VERSION 5.8 ;
BUSBITCHARS "[]" ;
DIVIDERCHAR "/" ;
UNITS
    DATABASE MICRONS 1000 ;
END UNITS

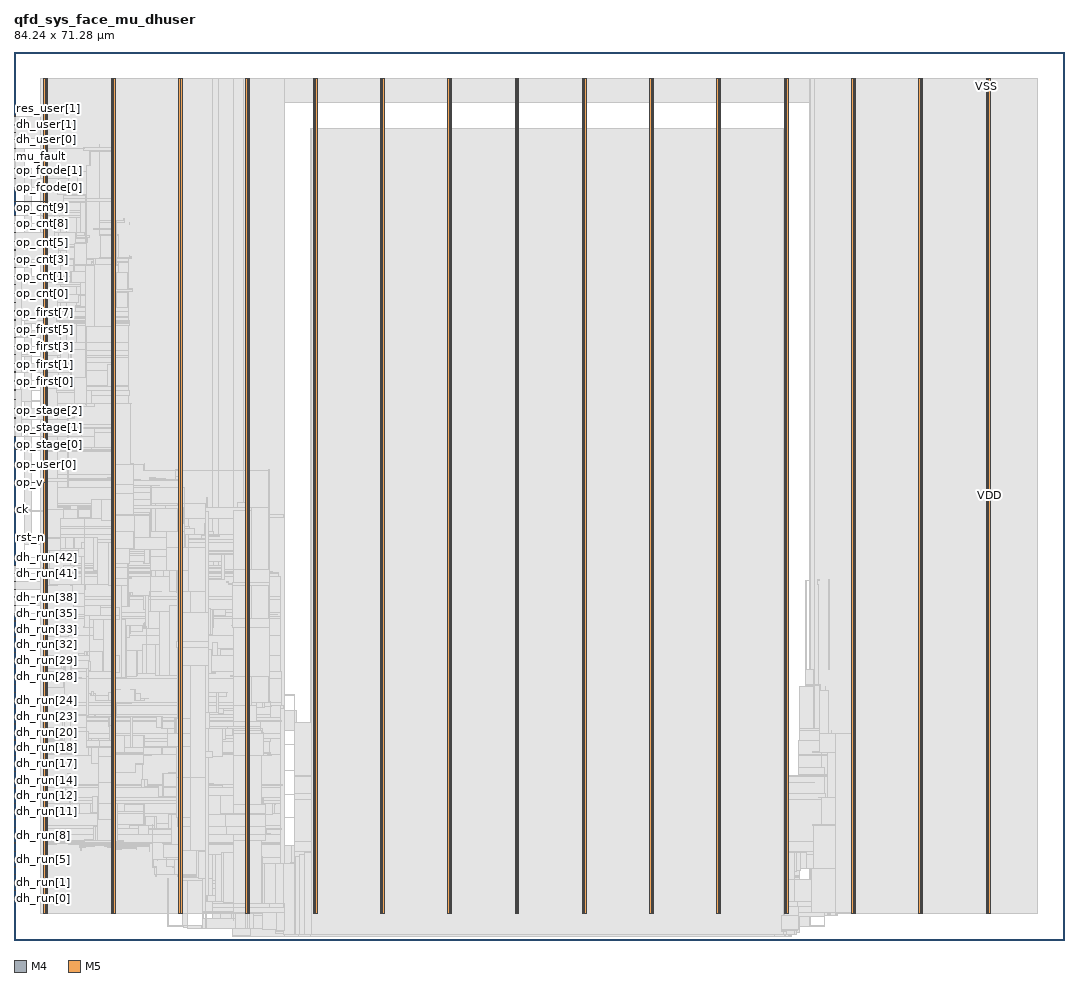
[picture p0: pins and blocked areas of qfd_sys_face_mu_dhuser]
MACRO qfd_sys_face_mu_dhuser
  FOREIGN qfd_sys_face_mu_dhuser 0 0 ;
  CLASS BLOCK ;
  SIZE 84.24 BY 71.28 ;
  PIN ck
    DIRECTION INPUT ;
    USE SIGNAL ;
    PORT
      LAYER M4 ;
        RECT  0 34.512 0.084 34.536 ;
    END
    PORT
      LAYER M4 ;
        RECT  0.06 34.512 0.097 34.536 ;
    END
  END ck
  PIN dh_run[0]
    DIRECTION INPUT ;
    USE SIGNAL ;
    PORT
      LAYER M4 ;
        RECT  0 3.312 0.084 3.336 ;
    END
  END dh_run[0]
  PIN dh_run[10]
    DIRECTION INPUT ;
    USE SIGNAL ;
    PORT
      LAYER M4 ;
        RECT  0 9.648 0.084 9.672 ;
    END
  END dh_run[10]
  PIN dh_run[11]
    DIRECTION INPUT ;
    USE SIGNAL ;
    PORT
      LAYER M4 ;
        RECT  0 10.32 0.084 10.344 ;
    END
  END dh_run[11]
  PIN dh_run[12]
    DIRECTION INPUT ;
    USE SIGNAL ;
    PORT
      LAYER M4 ;
        RECT  0 10.944 0.084 10.968 ;
    END
  END dh_run[12]
  PIN dh_run[13]
    DIRECTION INPUT ;
    USE SIGNAL ;
    PORT
      LAYER M4 ;
        RECT  0 11.568 0.084 11.592 ;
    END
  END dh_run[13]
  PIN dh_run[14]
    DIRECTION INPUT ;
    USE SIGNAL ;
    PORT
      LAYER M4 ;
        RECT  0 12.192 0.084 12.216 ;
    END
  END dh_run[14]
  PIN dh_run[15]
    DIRECTION INPUT ;
    USE SIGNAL ;
    PORT
      LAYER M4 ;
        RECT  0 12.864 0.084 12.888 ;
    END
  END dh_run[15]
  PIN dh_run[16]
    DIRECTION INPUT ;
    USE SIGNAL ;
    PORT
      LAYER M4 ;
        RECT  0 13.488 0.084 13.512 ;
    END
  END dh_run[16]
  PIN dh_run[17]
    DIRECTION INPUT ;
    USE SIGNAL ;
    PORT
      LAYER M4 ;
        RECT  0 14.112 0.084 14.136 ;
    END
  END dh_run[17]
  PIN dh_run[18]
    DIRECTION INPUT ;
    USE SIGNAL ;
    PORT
      LAYER M4 ;
        RECT  0 14.784 0.084 14.808 ;
    END
  END dh_run[18]
  PIN dh_run[19]
    DIRECTION INPUT ;
    USE SIGNAL ;
    PORT
      LAYER M4 ;
        RECT  0 15.408 0.084 15.432 ;
    END
  END dh_run[19]
  PIN dh_run[1]
    DIRECTION INPUT ;
    USE SIGNAL ;
    PORT
      LAYER M4 ;
        RECT  0 3.936 0.084 3.96 ;
    END
  END dh_run[1]
  PIN dh_run[20]
    DIRECTION INPUT ;
    USE SIGNAL ;
    PORT
      LAYER M4 ;
        RECT  0 16.032 0.084 16.056 ;
    END
  END dh_run[20]
  PIN dh_run[21]
    DIRECTION INPUT ;
    USE SIGNAL ;
    PORT
      LAYER M4 ;
        RECT  0 16.656 0.084 16.68 ;
    END
  END dh_run[21]
  PIN dh_run[22]
    DIRECTION INPUT ;
    USE SIGNAL ;
    PORT
      LAYER M4 ;
        RECT  0 17.328 0.084 17.352 ;
    END
  END dh_run[22]
  PIN dh_run[23]
    DIRECTION INPUT ;
    USE SIGNAL ;
    PORT
      LAYER M4 ;
        RECT  0 17.952 0.084 17.976 ;
    END
  END dh_run[23]
  PIN dh_run[24]
    DIRECTION INPUT ;
    USE SIGNAL ;
    PORT
      LAYER M4 ;
        RECT  0 18.576 0.084 18.6 ;
    END
  END dh_run[24]
  PIN dh_run[25]
    DIRECTION INPUT ;
    USE SIGNAL ;
    PORT
      LAYER M4 ;
        RECT  0 19.2 0.084 19.224 ;
    END
  END dh_run[25]
  PIN dh_run[26]
    DIRECTION INPUT ;
    USE SIGNAL ;
    PORT
      LAYER M4 ;
        RECT  0 19.872 0.084 19.896 ;
    END
  END dh_run[26]
  PIN dh_run[27]
    DIRECTION INPUT ;
    USE SIGNAL ;
    PORT
      LAYER M4 ;
        RECT  0 20.496 0.084 20.52 ;
    END
  END dh_run[27]
  PIN dh_run[28]
    DIRECTION INPUT ;
    USE SIGNAL ;
    PORT
      LAYER M4 ;
        RECT  0 21.12 0.084 21.144 ;
    END
  END dh_run[28]
  PIN dh_run[29]
    DIRECTION INPUT ;
    USE SIGNAL ;
    PORT
      LAYER M4 ;
        RECT  0 21.744 0.084 21.768 ;
    END
  END dh_run[29]
  PIN dh_run[2]
    DIRECTION INPUT ;
    USE SIGNAL ;
    PORT
      LAYER M4 ;
        RECT  0 4.56 0.084 4.584 ;
    END
  END dh_run[2]
  PIN dh_run[30]
    DIRECTION INPUT ;
    USE SIGNAL ;
    PORT
      LAYER M4 ;
        RECT  0 22.416 0.084 22.44 ;
    END
  END dh_run[30]
  PIN dh_run[31]
    DIRECTION INPUT ;
    USE SIGNAL ;
    PORT
      LAYER M4 ;
        RECT  0 23.04 0.084 23.064 ;
    END
  END dh_run[31]
  PIN dh_run[32]
    DIRECTION INPUT ;
    USE SIGNAL ;
    PORT
      LAYER M4 ;
        RECT  0 23.664 0.084 23.688 ;
    END
  END dh_run[32]
  PIN dh_run[33]
    DIRECTION INPUT ;
    USE SIGNAL ;
    PORT
      LAYER M4 ;
        RECT  0 24.288 0.084 24.312 ;
    END
  END dh_run[33]
  PIN dh_run[34]
    DIRECTION INPUT ;
    USE SIGNAL ;
    PORT
      LAYER M4 ;
        RECT  0 24.96 0.084 24.984 ;
    END
  END dh_run[34]
  PIN dh_run[35]
    DIRECTION INPUT ;
    USE SIGNAL ;
    PORT
      LAYER M4 ;
        RECT  0 25.584 0.084 25.608 ;
    END
  END dh_run[35]
  PIN dh_run[36]
    DIRECTION INPUT ;
    USE SIGNAL ;
    PORT
      LAYER M4 ;
        RECT  0 26.208 0.084 26.232 ;
    END
  END dh_run[36]
  PIN dh_run[37]
    DIRECTION INPUT ;
    USE SIGNAL ;
    PORT
      LAYER M4 ;
        RECT  0 26.832 0.084 26.856 ;
    END
  END dh_run[37]
  PIN dh_run[38]
    DIRECTION INPUT ;
    USE SIGNAL ;
    PORT
      LAYER M4 ;
        RECT  0 27.504 0.084 27.528 ;
    END
  END dh_run[38]
  PIN dh_run[39]
    DIRECTION INPUT ;
    USE SIGNAL ;
    PORT
      LAYER M4 ;
        RECT  0 28.128 0.084 28.152 ;
    END
  END dh_run[39]
  PIN dh_run[3]
    DIRECTION INPUT ;
    USE SIGNAL ;
    PORT
      LAYER M4 ;
        RECT  0 5.232 0.084 5.256 ;
    END
  END dh_run[3]
  PIN dh_run[40]
    DIRECTION INPUT ;
    USE SIGNAL ;
    PORT
      LAYER M4 ;
        RECT  0 28.752 0.084 28.776 ;
    END
  END dh_run[40]
  PIN dh_run[41]
    DIRECTION INPUT ;
    USE SIGNAL ;
    PORT
      LAYER M4 ;
        RECT  0 29.376 0.084 29.4 ;
    END
  END dh_run[41]
  PIN dh_run[42]
    DIRECTION INPUT ;
    USE SIGNAL ;
    PORT
      LAYER M4 ;
        RECT  0 30.048 0.084 30.072 ;
    END
  END dh_run[42]
  PIN dh_run[43]
    DIRECTION INPUT ;
    USE SIGNAL ;
    PORT
      LAYER M4 ;
        RECT  0 30.672 0.084 30.696 ;
    END
  END dh_run[43]
  PIN dh_run[4]
    DIRECTION INPUT ;
    USE SIGNAL ;
    PORT
      LAYER M4 ;
        RECT  0 5.856 0.084 5.88 ;
    END
  END dh_run[4]
  PIN dh_run[5]
    DIRECTION INPUT ;
    USE SIGNAL ;
    PORT
      LAYER M4 ;
        RECT  0 6.48 0.084 6.504 ;
    END
  END dh_run[5]
  PIN dh_run[6]
    DIRECTION INPUT ;
    USE SIGNAL ;
    PORT
      LAYER M4 ;
        RECT  0 7.104 0.084 7.128 ;
    END
  END dh_run[6]
  PIN dh_run[7]
    DIRECTION INPUT ;
    USE SIGNAL ;
    PORT
      LAYER M4 ;
        RECT  0 7.776 0.084 7.8 ;
    END
  END dh_run[7]
  PIN dh_run[8]
    DIRECTION INPUT ;
    USE SIGNAL ;
    PORT
      LAYER M4 ;
        RECT  0 8.4 0.084 8.424 ;
    END
  END dh_run[8]
  PIN dh_run[9]
    DIRECTION INPUT ;
    USE SIGNAL ;
    PORT
      LAYER M4 ;
        RECT  0 9.024 0.084 9.048 ;
    END
  END dh_run[9]
  PIN dh_user[0]
    DIRECTION OUTPUT ;
    USE SIGNAL ;
    PORT
      LAYER M4 ;
        RECT  0 64.224 0.084 64.248 ;
    END
  END dh_user[0]
  PIN dh_user[1]
    DIRECTION OUTPUT ;
    USE SIGNAL ;
    PORT
      LAYER M4 ;
        RECT  0 64.752 0.084 64.776 ;
    END
  END dh_user[1]
  PIN mu_fault
    DIRECTION OUTPUT ;
    USE SIGNAL ;
    PORT
      LAYER M4 ;
        RECT  0 63.504 0.084 63.528 ;
    END
  END mu_fault
  PIN op_cnt[0]
    DIRECTION OUTPUT ;
    USE SIGNAL ;
    PORT
      LAYER M4 ;
        RECT  0 51.84 0.084 51.864 ;
    END
  END op_cnt[0]
  PIN op_cnt[1]
    DIRECTION OUTPUT ;
    USE SIGNAL ;
    PORT
      LAYER M4 ;
        RECT  0 52.56 0.084 52.584 ;
    END
  END op_cnt[1]
  PIN op_cnt[2]
    DIRECTION OUTPUT ;
    USE SIGNAL ;
    PORT
      LAYER M4 ;
        RECT  0 53.232 0.084 53.256 ;
    END
  END op_cnt[2]
  PIN op_cnt[3]
    DIRECTION OUTPUT ;
    USE SIGNAL ;
    PORT
      LAYER M4 ;
        RECT  0 53.952 0.084 53.976 ;
    END
  END op_cnt[3]
  PIN op_cnt[4]
    DIRECTION OUTPUT ;
    USE SIGNAL ;
    PORT
      LAYER M4 ;
        RECT  0 54.624 0.084 54.648 ;
    END
  END op_cnt[4]
  PIN op_cnt[5]
    DIRECTION OUTPUT ;
    USE SIGNAL ;
    PORT
      LAYER M4 ;
        RECT  0 55.344 0.084 55.368 ;
    END
  END op_cnt[5]
  PIN op_cnt[6]
    DIRECTION OUTPUT ;
    USE SIGNAL ;
    PORT
      LAYER M4 ;
        RECT  0 56.016 0.084 56.04 ;
    END
  END op_cnt[6]
  PIN op_cnt[7]
    DIRECTION OUTPUT ;
    USE SIGNAL ;
    PORT
      LAYER M4 ;
        RECT  0 56.736 0.084 56.76 ;
    END
  END op_cnt[7]
  PIN op_cnt[8]
    DIRECTION OUTPUT ;
    USE SIGNAL ;
    PORT
      LAYER M4 ;
        RECT  0 57.456 0.084 57.48 ;
    END
  END op_cnt[8]
  PIN op_cnt[9]
    DIRECTION OUTPUT ;
    USE SIGNAL ;
    PORT
      LAYER M4 ;
        RECT  0 58.128 0.084 58.152 ;
    END
  END op_cnt[9]
  PIN op_fcode[0]
    DIRECTION OUTPUT ;
    USE SIGNAL ;
    PORT
      LAYER M4 ;
        RECT  0 60.384 0.084 60.408 ;
    END
  END op_fcode[0]
  PIN op_fcode[1]
    DIRECTION OUTPUT ;
    USE SIGNAL ;
    PORT
      LAYER M4 ;
        RECT  0 61.104 0.084 61.128 ;
    END
  END op_fcode[1]
  PIN op_fcode[2]
    DIRECTION OUTPUT ;
    USE SIGNAL ;
    PORT
      LAYER M4 ;
        RECT  0 61.872 0.084 61.896 ;
    END
  END op_fcode[2]
  PIN op_fcode[3]
    DIRECTION OUTPUT ;
    USE SIGNAL ;
    PORT
      LAYER M4 ;
        RECT  0 62.592 0.084 62.616 ;
    END
  END op_fcode[3]
  PIN op_ff
    DIRECTION OUTPUT ;
    USE SIGNAL ;
    PORT
      LAYER M4 ;
        RECT  0 59.232 0.084 59.256 ;
    END
    PORT
      LAYER M4 ;
        RECT  0.06 59.232 2.408 59.256 ;
    END
  END op_ff
  PIN op_first[0]
    DIRECTION OUTPUT ;
    USE SIGNAL ;
    PORT
      LAYER M4 ;
        RECT  0 44.832 0.084 44.856 ;
    END
  END op_first[0]
  PIN op_first[1]
    DIRECTION OUTPUT ;
    USE SIGNAL ;
    PORT
      LAYER M4 ;
        RECT  0 45.552 0.084 45.576 ;
    END
  END op_first[1]
  PIN op_first[2]
    DIRECTION OUTPUT ;
    USE SIGNAL ;
    PORT
      LAYER M4 ;
        RECT  0 46.224 0.084 46.248 ;
    END
  END op_first[2]
  PIN op_first[3]
    DIRECTION OUTPUT ;
    USE SIGNAL ;
    PORT
      LAYER M4 ;
        RECT  0 46.944 0.084 46.968 ;
    END
  END op_first[3]
  PIN op_first[4]
    DIRECTION OUTPUT ;
    USE SIGNAL ;
    PORT
      LAYER M4 ;
        RECT  0 47.616 0.084 47.64 ;
    END
  END op_first[4]
  PIN op_first[5]
    DIRECTION OUTPUT ;
    USE SIGNAL ;
    PORT
      LAYER M4 ;
        RECT  0 48.336 0.084 48.36 ;
    END
  END op_first[5]
  PIN op_first[6]
    DIRECTION OUTPUT ;
    USE SIGNAL ;
    PORT
      LAYER M4 ;
        RECT  0 49.056 0.084 49.08 ;
    END
  END op_first[6]
  PIN op_first[7]
    DIRECTION OUTPUT ;
    USE SIGNAL ;
    PORT
      LAYER M4 ;
        RECT  0 49.728 0.084 49.752 ;
    END
  END op_first[7]
  PIN op_first[8]
    DIRECTION OUTPUT ;
    USE SIGNAL ;
    PORT
      LAYER M4 ;
        RECT  0 50.448 0.084 50.472 ;
    END
  END op_first[8]
  PIN op_first[9]
    DIRECTION OUTPUT ;
    USE SIGNAL ;
    PORT
      LAYER M4 ;
        RECT  0 51.12 0.084 51.144 ;
    END
  END op_first[9]
  PIN op_stage[0]
    DIRECTION OUTPUT ;
    USE SIGNAL ;
    PORT
      LAYER M4 ;
        RECT  0 40.368 0.084 40.392 ;
    END
  END op_stage[0]
  PIN op_stage[1]
    DIRECTION OUTPUT ;
    USE SIGNAL ;
    PORT
      LAYER M4 ;
        RECT  0 41.136 0.084 41.16 ;
    END
  END op_stage[1]
  PIN op_stage[2]
    DIRECTION OUTPUT ;
    USE SIGNAL ;
    PORT
      LAYER M4 ;
        RECT  0 41.856 0.084 41.88 ;
    END
  END op_stage[2]
  PIN op_stage[3]
    DIRECTION OUTPUT ;
    USE SIGNAL ;
    PORT
      LAYER M4 ;
        RECT  0 42.624 0.084 42.648 ;
    END
  END op_stage[3]
  PIN op_stage[4]
    DIRECTION OUTPUT ;
    USE SIGNAL ;
    PORT
      LAYER M4 ;
        RECT  0 43.344 0.084 43.368 ;
    END
  END op_stage[4]
  PIN op_stage[5]
    DIRECTION OUTPUT ;
    USE SIGNAL ;
    PORT
      LAYER M4 ;
        RECT  0 44.112 0.084 44.136 ;
    END
  END op_stage[5]
  PIN op_user[0]
    DIRECTION OUTPUT ;
    USE SIGNAL ;
    PORT
      LAYER M4 ;
        RECT  0 38.112 0.084 38.136 ;
    END
    PORT
      LAYER M4 ;
        RECT  0.06 38.112 2.408 38.136 ;
    END
  END op_user[0]
  PIN op_user[1]
    DIRECTION OUTPUT ;
    USE SIGNAL ;
    PORT
      LAYER M4 ;
        RECT  0 39.36 0.084 39.384 ;
    END
    PORT
      LAYER M4 ;
        RECT  0.06 39.36 0.569 39.384 ;
    END
  END op_user[1]
  PIN op_v
    DIRECTION OUTPUT ;
    USE SIGNAL ;
    PORT
      LAYER M4 ;
        RECT  0 36.72 0.084 36.744 ;
    END
    PORT
      LAYER M4 ;
        RECT  0.06 36.72 2.408 36.744 ;
    END
  END op_v
  PIN res_user[0]
    DIRECTION OUTPUT ;
    USE SIGNAL ;
    PORT
      LAYER M4 ;
        RECT  0 65.376 0.084 65.4 ;
    END
  END res_user[0]
  PIN res_user[1]
    DIRECTION OUTPUT ;
    USE SIGNAL ;
    PORT
      LAYER M4 ;
        RECT  0 66.096 0.084 66.12 ;
    END
  END res_user[1]
  PIN rst_n
    DIRECTION INPUT ;
    USE SIGNAL ;
    PORT
      LAYER M4 ;
        RECT  0 32.256 0.084 32.28 ;
    END
    PORT
      LAYER M4 ;
        RECT  0.06 32.256 2.408 32.28 ;
    END
  END rst_n
  PIN VDD
    DIRECTION INOUT ;
    USE POWER ;
    PORT
      LAYER M5 ;
        RECT  78.192 2.151 78.312 69.129 ;
        RECT  72.792 2.151 72.912 69.129 ;
        RECT  67.392 2.151 67.512 69.129 ;
        RECT  61.992 2.151 62.112 69.129 ;
        RECT  56.592 2.151 56.712 69.129 ;
        RECT  51.192 2.151 51.312 69.129 ;
        RECT  45.792 2.151 45.912 69.129 ;
        RECT  40.392 2.151 40.512 69.129 ;
        RECT  34.992 2.151 35.112 69.129 ;
        RECT  29.592 2.151 29.712 69.129 ;
        RECT  24.192 2.151 24.312 69.129 ;
        RECT  18.792 2.151 18.912 69.129 ;
        RECT  13.392 2.151 13.512 69.129 ;
        RECT  7.992 2.151 8.112 69.129 ;
        RECT  2.592 2.151 2.712 69.129 ;
    END
  END VDD
  PIN VSS
    DIRECTION INOUT ;
    USE GROUND ;
    PORT
      LAYER M5 ;
        RECT  78 2.137 78.12 69.143 ;
        RECT  72.6 2.137 72.72 69.143 ;
        RECT  67.2 2.137 67.32 69.143 ;
        RECT  61.8 2.151 61.92 69.143 ;
        RECT  56.4 2.151 56.52 69.143 ;
        RECT  51 2.151 51.12 69.143 ;
        RECT  45.6 2.151 45.72 69.143 ;
        RECT  40.2 2.151 40.32 69.143 ;
        RECT  34.8 2.151 34.92 69.143 ;
        RECT  29.4 2.151 29.52 69.143 ;
        RECT  24 2.151 24.12 69.143 ;
        RECT  18.6 2.137 18.72 69.143 ;
        RECT  13.2 2.137 13.32 69.143 ;
        RECT  7.8 2.137 7.92 69.143 ;
        RECT  2.4 2.137 2.52 69.143 ;
    END
  END VSS
  # OT_OBS_CLOSED layer=M5 d_um=1.536 added=63
  OBS
    LAYER RVTN ;
     RECT  2.16 2.16 21.708 2.295 ;
     RECT  63.828 2.16 82.08 2.295 ;
     RECT  2.16 2.565 21.708 2.835 ;
     RECT  63.828 2.565 82.08 2.835 ;
     RECT  2.16 3.105 21.708 3.375 ;
     RECT  63.828 3.105 82.08 3.375 ;
     RECT  2.16 3.645 21.708 3.915 ;
     RECT  63.828 3.645 82.08 3.915 ;
     RECT  2.16 4.185 21.708 4.455 ;
     RECT  63.828 4.185 82.08 4.455 ;
     RECT  2.16 4.725 21.708 4.995 ;
     RECT  63.828 4.725 82.08 4.995 ;
     RECT  2.16 5.265 21.708 5.535 ;
     RECT  63.828 5.265 82.08 5.535 ;
     RECT  2.16 5.805 21.708 6.075 ;
     RECT  63.828 5.805 82.08 6.075 ;
     RECT  2.16 6.345 21.708 6.615 ;
     RECT  63.828 6.345 82.08 6.615 ;
     RECT  2.16 6.885 21.708 7.155 ;
     RECT  63.828 6.885 82.08 7.155 ;
     RECT  2.16 7.425 21.708 7.695 ;
     RECT  63.828 7.425 82.08 7.695 ;
     RECT  2.16 7.965 21.708 8.235 ;
     RECT  63.828 7.965 82.08 8.235 ;
     RECT  2.16 8.505 21.708 8.775 ;
     RECT  63.828 8.505 82.08 8.775 ;
     RECT  2.16 9.045 21.708 9.315 ;
     RECT  63.828 9.045 82.08 9.315 ;
     RECT  2.16 9.585 21.708 9.855 ;
     RECT  63.828 9.585 82.08 9.855 ;
     RECT  2.16 10.125 21.708 10.395 ;
     RECT  63.828 10.125 82.08 10.395 ;
     RECT  2.16 10.665 21.708 10.935 ;
     RECT  63.828 10.665 82.08 10.935 ;
     RECT  2.16 11.205 21.708 11.475 ;
     RECT  63.828 11.205 82.08 11.475 ;
     RECT  2.16 11.745 21.708 12.015 ;
     RECT  63.828 11.745 82.08 12.015 ;
     RECT  2.16 12.285 21.708 12.555 ;
     RECT  63.828 12.285 82.08 12.555 ;
     RECT  2.16 12.825 21.708 13.095 ;
     RECT  63.828 12.825 82.08 13.095 ;
     RECT  2.16 13.365 21.708 13.635 ;
     RECT  63.828 13.365 82.08 13.635 ;
     RECT  2.16 13.905 21.708 14.175 ;
     RECT  63.828 13.905 82.08 14.175 ;
     RECT  2.16 14.445 21.708 14.715 ;
     RECT  63.828 14.445 82.08 14.715 ;
     RECT  2.16 14.985 21.708 15.255 ;
     RECT  63.828 14.985 82.08 15.255 ;
     RECT  2.16 15.525 21.708 15.795 ;
     RECT  63.828 15.525 82.08 15.795 ;
     RECT  2.16 16.065 21.708 16.335 ;
     RECT  63.828 16.065 82.08 16.335 ;
     RECT  2.16 16.605 21.708 16.875 ;
     RECT  63.828 16.605 82.08 16.875 ;
     RECT  2.16 17.145 21.708 17.415 ;
     RECT  63.828 17.145 82.08 17.415 ;
     RECT  2.16 17.685 21.708 17.955 ;
     RECT  63.828 17.685 82.08 17.955 ;
     RECT  2.16 18.225 21.708 18.495 ;
     RECT  63.828 18.225 82.08 18.495 ;
     RECT  2.16 18.765 21.708 19.035 ;
     RECT  63.828 18.765 82.08 19.035 ;
     RECT  2.16 19.305 21.708 19.575 ;
     RECT  63.828 19.305 82.08 19.575 ;
     RECT  2.16 19.845 21.708 20.115 ;
     RECT  63.828 19.845 82.08 20.115 ;
     RECT  2.16 20.385 21.708 20.655 ;
     RECT  63.828 20.385 82.08 20.655 ;
     RECT  2.16 20.925 21.708 21.195 ;
     RECT  63.828 20.925 82.08 21.195 ;
     RECT  2.16 21.465 21.708 21.735 ;
     RECT  63.828 21.465 82.08 21.735 ;
     RECT  2.16 22.005 21.708 22.275 ;
     RECT  63.828 22.005 82.08 22.275 ;
     RECT  2.16 22.545 21.708 22.815 ;
     RECT  63.828 22.545 82.08 22.815 ;
     RECT  2.16 23.085 21.708 23.355 ;
     RECT  63.828 23.085 82.08 23.355 ;
     RECT  2.16 23.625 21.708 23.895 ;
     RECT  63.828 23.625 82.08 23.895 ;
     RECT  2.16 24.165 21.708 24.435 ;
     RECT  63.828 24.165 82.08 24.435 ;
     RECT  2.16 24.705 21.708 24.975 ;
     RECT  63.828 24.705 82.08 24.975 ;
     RECT  2.16 25.245 21.708 25.515 ;
     RECT  63.828 25.245 82.08 25.515 ;
     RECT  2.16 25.785 21.708 26.055 ;
     RECT  63.828 25.785 82.08 26.055 ;
     RECT  2.16 26.325 21.708 26.595 ;
     RECT  63.828 26.325 82.08 26.595 ;
     RECT  2.16 26.865 21.708 27.135 ;
     RECT  63.828 26.865 82.08 27.135 ;
     RECT  2.16 27.405 21.708 27.675 ;
     RECT  63.828 27.405 82.08 27.675 ;
     RECT  2.16 27.945 21.708 28.215 ;
     RECT  63.828 27.945 82.08 28.215 ;
     RECT  2.16 28.485 21.708 28.755 ;
     RECT  63.828 28.485 82.08 28.755 ;
     RECT  2.16 29.025 21.708 29.295 ;
     RECT  63.828 29.025 82.08 29.295 ;
     RECT  2.16 29.565 21.708 29.835 ;
     RECT  63.828 29.565 82.08 29.835 ;
     RECT  2.16 30.105 21.708 30.375 ;
     RECT  63.828 30.105 82.08 30.375 ;
     RECT  2.16 30.645 21.708 30.915 ;
     RECT  63.828 30.645 82.08 30.915 ;
     RECT  2.16 31.185 21.708 31.455 ;
     RECT  63.828 31.185 82.08 31.455 ;
     RECT  2.16 31.725 21.708 31.995 ;
     RECT  63.828 31.725 82.08 31.995 ;
     RECT  2.16 32.265 21.708 32.535 ;
     RECT  63.828 32.265 82.08 32.535 ;
     RECT  2.16 32.805 21.708 33.075 ;
     RECT  63.828 32.805 82.08 33.075 ;
     RECT  2.16 33.345 21.708 33.615 ;
     RECT  63.828 33.345 82.08 33.615 ;
     RECT  2.16 33.885 21.708 34.155 ;
     RECT  63.828 33.885 82.08 34.155 ;
     RECT  2.16 34.425 21.708 34.695 ;
     RECT  63.828 34.425 82.08 34.695 ;
     RECT  2.16 34.965 21.708 35.235 ;
     RECT  63.828 34.965 82.08 35.235 ;
     RECT  2.16 35.505 21.708 35.775 ;
     RECT  63.828 35.505 82.08 35.775 ;
     RECT  2.16 36.045 21.708 36.315 ;
     RECT  63.828 36.045 82.08 36.315 ;
     RECT  2.16 36.585 21.708 36.855 ;
     RECT  63.828 36.585 82.08 36.855 ;
     RECT  2.16 37.125 21.708 37.395 ;
     RECT  63.828 37.125 82.08 37.395 ;
     RECT  2.16 37.665 21.708 37.935 ;
     RECT  63.828 37.665 82.08 37.935 ;
     RECT  2.16 38.205 21.708 38.475 ;
     RECT  63.828 38.205 82.08 38.475 ;
     RECT  2.16 38.745 21.708 39.015 ;
     RECT  63.828 38.745 82.08 39.015 ;
     RECT  2.16 39.285 21.708 39.555 ;
     RECT  63.828 39.285 82.08 39.555 ;
     RECT  2.16 39.825 21.708 40.095 ;
     RECT  63.828 39.825 82.08 40.095 ;
     RECT  2.16 40.365 21.708 40.635 ;
     RECT  63.828 40.365 82.08 40.635 ;
     RECT  2.16 40.905 21.708 41.175 ;
     RECT  63.828 40.905 82.08 41.175 ;
     RECT  2.16 41.445 21.708 41.715 ;
     RECT  63.828 41.445 82.08 41.715 ;
     RECT  2.16 41.985 21.708 42.255 ;
     RECT  63.828 41.985 82.08 42.255 ;
     RECT  2.16 42.525 21.708 42.795 ;
     RECT  63.828 42.525 82.08 42.795 ;
     RECT  2.16 43.065 21.708 43.335 ;
     RECT  63.828 43.065 82.08 43.335 ;
     RECT  2.16 43.605 21.708 43.875 ;
     RECT  63.828 43.605 82.08 43.875 ;
     RECT  2.16 44.145 21.708 44.415 ;
     RECT  63.828 44.145 82.08 44.415 ;
     RECT  2.16 44.685 21.708 44.955 ;
     RECT  63.828 44.685 82.08 44.955 ;
     RECT  2.16 45.225 21.708 45.495 ;
     RECT  63.828 45.225 82.08 45.495 ;
     RECT  2.16 45.765 21.708 46.035 ;
     RECT  63.828 45.765 82.08 46.035 ;
     RECT  2.16 46.305 21.708 46.575 ;
     RECT  63.828 46.305 82.08 46.575 ;
     RECT  2.16 46.845 21.708 47.115 ;
     RECT  63.828 46.845 82.08 47.115 ;
     RECT  2.16 47.385 21.708 47.655 ;
     RECT  63.828 47.385 82.08 47.655 ;
     RECT  2.16 47.925 21.708 48.195 ;
     RECT  63.828 47.925 82.08 48.195 ;
     RECT  2.16 48.465 21.708 48.735 ;
     RECT  63.828 48.465 82.08 48.735 ;
     RECT  2.16 49.005 21.708 49.275 ;
     RECT  63.828 49.005 82.08 49.275 ;
     RECT  2.16 49.545 21.708 49.815 ;
     RECT  63.828 49.545 82.08 49.815 ;
     RECT  2.16 50.085 21.708 50.355 ;
     RECT  63.828 50.085 82.08 50.355 ;
     RECT  2.16 50.625 21.708 50.895 ;
     RECT  63.828 50.625 82.08 50.895 ;
     RECT  2.16 51.165 21.708 51.435 ;
     RECT  63.828 51.165 82.08 51.435 ;
     RECT  2.16 51.705 21.708 51.975 ;
     RECT  63.828 51.705 82.08 51.975 ;
     RECT  2.16 52.245 21.708 52.515 ;
     RECT  63.828 52.245 82.08 52.515 ;
     RECT  2.16 52.785 21.708 53.055 ;
     RECT  63.828 52.785 82.08 53.055 ;
     RECT  2.16 53.325 21.708 53.595 ;
     RECT  63.828 53.325 82.08 53.595 ;
     RECT  2.16 53.865 21.708 54.135 ;
     RECT  63.828 53.865 82.08 54.135 ;
     RECT  2.16 54.405 21.708 54.675 ;
     RECT  63.828 54.405 82.08 54.675 ;
     RECT  2.16 54.945 21.708 55.215 ;
     RECT  63.828 54.945 82.08 55.215 ;
     RECT  2.16 55.485 21.708 55.755 ;
     RECT  63.828 55.485 82.08 55.755 ;
     RECT  2.16 56.025 21.708 56.295 ;
     RECT  63.828 56.025 82.08 56.295 ;
     RECT  2.16 56.565 21.708 56.835 ;
     RECT  63.828 56.565 82.08 56.835 ;
     RECT  2.16 57.105 21.708 57.375 ;
     RECT  63.828 57.105 82.08 57.375 ;
     RECT  2.16 57.645 21.708 57.915 ;
     RECT  63.828 57.645 82.08 57.915 ;
     RECT  2.16 58.185 21.708 58.455 ;
     RECT  63.828 58.185 82.08 58.455 ;
     RECT  2.16 58.725 21.708 58.995 ;
     RECT  63.828 58.725 82.08 58.995 ;
     RECT  2.16 59.265 21.708 59.535 ;
     RECT  63.828 59.265 82.08 59.535 ;
     RECT  2.16 59.805 21.708 60.075 ;
     RECT  63.828 59.805 82.08 60.075 ;
     RECT  2.16 60.345 21.708 60.615 ;
     RECT  63.828 60.345 82.08 60.615 ;
     RECT  2.16 60.885 21.708 61.155 ;
     RECT  63.828 60.885 82.08 61.155 ;
     RECT  2.16 61.425 21.708 61.695 ;
     RECT  63.828 61.425 82.08 61.695 ;
     RECT  2.16 61.965 21.708 62.235 ;
     RECT  63.828 61.965 82.08 62.235 ;
     RECT  2.16 62.505 21.708 62.775 ;
     RECT  63.828 62.505 82.08 62.775 ;
     RECT  2.16 63.045 21.708 63.315 ;
     RECT  63.828 63.045 82.08 63.315 ;
     RECT  2.16 63.585 21.708 63.855 ;
     RECT  63.828 63.585 82.08 63.855 ;
     RECT  2.16 64.125 21.708 64.395 ;
     RECT  63.828 64.125 82.08 64.395 ;
     RECT  2.16 64.665 21.708 64.935 ;
     RECT  63.828 64.665 82.08 64.935 ;
     RECT  2.16 65.205 21.708 65.475 ;
     RECT  63.828 65.205 82.08 65.475 ;
     RECT  2.16 65.745 21.708 66.015 ;
     RECT  63.828 65.745 82.08 66.015 ;
     RECT  2.16 66.285 21.708 66.555 ;
     RECT  63.828 66.285 82.08 66.555 ;
     RECT  2.16 66.825 21.708 67.095 ;
     RECT  63.828 66.825 82.08 67.095 ;
     RECT  2.16 67.365 82.08 67.635 ;
     RECT  2.16 67.905 82.08 68.175 ;
     RECT  2.16 68.445 82.08 68.715 ;
     RECT  2.16 68.985 82.08 69.12 ;
    LAYER RVTP ;
     RECT  2.16 2.295 21.708 2.565 ;
     RECT  63.828 2.295 82.08 2.565 ;
     RECT  2.16 2.835 21.708 3.105 ;
     RECT  63.828 2.835 82.08 3.105 ;
     RECT  2.16 3.375 21.708 3.645 ;
     RECT  63.828 3.375 82.08 3.645 ;
     RECT  2.16 3.915 21.708 4.185 ;
     RECT  63.828 3.915 82.08 4.185 ;
     RECT  2.16 4.455 21.708 4.725 ;
     RECT  63.828 4.455 82.08 4.725 ;
     RECT  2.16 4.995 21.708 5.265 ;
     RECT  63.828 4.995 82.08 5.265 ;
     RECT  2.16 5.535 21.708 5.805 ;
     RECT  63.828 5.535 82.08 5.805 ;
     RECT  2.16 6.075 21.708 6.345 ;
     RECT  63.828 6.075 82.08 6.345 ;
     RECT  2.16 6.615 21.708 6.885 ;
     RECT  63.828 6.615 82.08 6.885 ;
     RECT  2.16 7.155 21.708 7.425 ;
     RECT  63.828 7.155 82.08 7.425 ;
     RECT  2.16 7.695 21.708 7.965 ;
     RECT  63.828 7.695 82.08 7.965 ;
     RECT  2.16 8.235 21.708 8.505 ;
     RECT  63.828 8.235 82.08 8.505 ;
     RECT  2.16 8.775 21.708 9.045 ;
     RECT  63.828 8.775 82.08 9.045 ;
     RECT  2.16 9.315 21.708 9.585 ;
     RECT  63.828 9.315 82.08 9.585 ;
     RECT  2.16 9.855 21.708 10.125 ;
     RECT  63.828 9.855 82.08 10.125 ;
     RECT  2.16 10.395 21.708 10.665 ;
     RECT  63.828 10.395 82.08 10.665 ;
     RECT  2.16 10.935 21.708 11.205 ;
     RECT  63.828 10.935 82.08 11.205 ;
     RECT  2.16 11.475 21.708 11.745 ;
     RECT  63.828 11.475 82.08 11.745 ;
     RECT  2.16 12.015 21.708 12.285 ;
     RECT  63.828 12.015 82.08 12.285 ;
     RECT  2.16 12.555 21.708 12.825 ;
     RECT  63.828 12.555 82.08 12.825 ;
     RECT  2.16 13.095 21.708 13.365 ;
     RECT  63.828 13.095 82.08 13.365 ;
     RECT  2.16 13.635 21.708 13.905 ;
     RECT  63.828 13.635 82.08 13.905 ;
     RECT  2.16 14.175 21.708 14.445 ;
     RECT  63.828 14.175 82.08 14.445 ;
     RECT  2.16 14.715 21.708 14.985 ;
     RECT  63.828 14.715 82.08 14.985 ;
     RECT  2.16 15.255 21.708 15.525 ;
     RECT  63.828 15.255 82.08 15.525 ;
     RECT  2.16 15.795 21.708 16.065 ;
     RECT  63.828 15.795 82.08 16.065 ;
     RECT  2.16 16.335 21.708 16.605 ;
     RECT  63.828 16.335 82.08 16.605 ;
     RECT  2.16 16.875 21.708 17.145 ;
     RECT  63.828 16.875 82.08 17.145 ;
     RECT  2.16 17.415 21.708 17.685 ;
     RECT  63.828 17.415 82.08 17.685 ;
     RECT  2.16 17.955 21.708 18.225 ;
     RECT  63.828 17.955 82.08 18.225 ;
     RECT  2.16 18.495 21.708 18.765 ;
     RECT  63.828 18.495 82.08 18.765 ;
     RECT  2.16 19.035 21.708 19.305 ;
     RECT  63.828 19.035 82.08 19.305 ;
     RECT  2.16 19.575 21.708 19.845 ;
     RECT  63.828 19.575 82.08 19.845 ;
     RECT  2.16 20.115 21.708 20.385 ;
     RECT  63.828 20.115 82.08 20.385 ;
     RECT  2.16 20.655 21.708 20.925 ;
     RECT  63.828 20.655 82.08 20.925 ;
     RECT  2.16 21.195 21.708 21.465 ;
     RECT  63.828 21.195 82.08 21.465 ;
     RECT  2.16 21.735 21.708 22.005 ;
     RECT  63.828 21.735 82.08 22.005 ;
     RECT  2.16 22.275 21.708 22.545 ;
     RECT  63.828 22.275 82.08 22.545 ;
     RECT  2.16 22.815 21.708 23.085 ;
     RECT  63.828 22.815 82.08 23.085 ;
     RECT  2.16 23.355 21.708 23.625 ;
     RECT  63.828 23.355 82.08 23.625 ;
     RECT  2.16 23.895 21.708 24.165 ;
     RECT  63.828 23.895 82.08 24.165 ;
     RECT  2.16 24.435 21.708 24.705 ;
     RECT  63.828 24.435 82.08 24.705 ;
     RECT  2.16 24.975 21.708 25.245 ;
     RECT  63.828 24.975 82.08 25.245 ;
     RECT  2.16 25.515 21.708 25.785 ;
     RECT  63.828 25.515 82.08 25.785 ;
     RECT  2.16 26.055 21.708 26.325 ;
     RECT  63.828 26.055 82.08 26.325 ;
     RECT  2.16 26.595 21.708 26.865 ;
     RECT  63.828 26.595 82.08 26.865 ;
     RECT  2.16 27.135 21.708 27.405 ;
     RECT  63.828 27.135 82.08 27.405 ;
     RECT  2.16 27.675 21.708 27.945 ;
     RECT  63.828 27.675 82.08 27.945 ;
     RECT  2.16 28.215 21.708 28.485 ;
     RECT  63.828 28.215 82.08 28.485 ;
     RECT  2.16 28.755 21.708 29.025 ;
     RECT  63.828 28.755 82.08 29.025 ;
     RECT  2.16 29.295 21.708 29.565 ;
     RECT  63.828 29.295 82.08 29.565 ;
     RECT  2.16 29.835 21.708 30.105 ;
     RECT  63.828 29.835 82.08 30.105 ;
     RECT  2.16 30.375 21.708 30.645 ;
     RECT  63.828 30.375 82.08 30.645 ;
     RECT  2.16 30.915 21.708 31.185 ;
     RECT  63.828 30.915 82.08 31.185 ;
     RECT  2.16 31.455 21.708 31.725 ;
     RECT  63.828 31.455 82.08 31.725 ;
     RECT  2.16 31.995 21.708 32.265 ;
     RECT  63.828 31.995 82.08 32.265 ;
     RECT  2.16 32.535 21.708 32.805 ;
     RECT  63.828 32.535 82.08 32.805 ;
     RECT  2.16 33.075 21.708 33.345 ;
     RECT  63.828 33.075 82.08 33.345 ;
     RECT  2.16 33.615 21.708 33.885 ;
     RECT  63.828 33.615 82.08 33.885 ;
     RECT  2.16 34.155 21.708 34.425 ;
     RECT  63.828 34.155 82.08 34.425 ;
     RECT  2.16 34.695 21.708 34.965 ;
     RECT  63.828 34.695 82.08 34.965 ;
     RECT  2.16 35.235 21.708 35.505 ;
     RECT  63.828 35.235 82.08 35.505 ;
     RECT  2.16 35.775 21.708 36.045 ;
     RECT  63.828 35.775 82.08 36.045 ;
     RECT  2.16 36.315 21.708 36.585 ;
     RECT  63.828 36.315 82.08 36.585 ;
     RECT  2.16 36.855 21.708 37.125 ;
     RECT  63.828 36.855 82.08 37.125 ;
     RECT  2.16 37.395 21.708 37.665 ;
     RECT  63.828 37.395 82.08 37.665 ;
     RECT  2.16 37.935 21.708 38.205 ;
     RECT  63.828 37.935 82.08 38.205 ;
     RECT  2.16 38.475 21.708 38.745 ;
     RECT  63.828 38.475 82.08 38.745 ;
     RECT  2.16 39.015 21.708 39.285 ;
     RECT  63.828 39.015 82.08 39.285 ;
     RECT  2.16 39.555 21.708 39.825 ;
     RECT  63.828 39.555 82.08 39.825 ;
     RECT  2.16 40.095 21.708 40.365 ;
     RECT  63.828 40.095 82.08 40.365 ;
     RECT  2.16 40.635 21.708 40.905 ;
     RECT  63.828 40.635 82.08 40.905 ;
     RECT  2.16 41.175 21.708 41.445 ;
     RECT  63.828 41.175 82.08 41.445 ;
     RECT  2.16 41.715 21.708 41.985 ;
     RECT  63.828 41.715 82.08 41.985 ;
     RECT  2.16 42.255 21.708 42.525 ;
     RECT  63.828 42.255 82.08 42.525 ;
     RECT  2.16 42.795 21.708 43.065 ;
     RECT  63.828 42.795 82.08 43.065 ;
     RECT  2.16 43.335 21.708 43.605 ;
     RECT  63.828 43.335 82.08 43.605 ;
     RECT  2.16 43.875 21.708 44.145 ;
     RECT  63.828 43.875 82.08 44.145 ;
     RECT  2.16 44.415 21.708 44.685 ;
     RECT  63.828 44.415 82.08 44.685 ;
     RECT  2.16 44.955 21.708 45.225 ;
     RECT  63.828 44.955 82.08 45.225 ;
     RECT  2.16 45.495 21.708 45.765 ;
     RECT  63.828 45.495 82.08 45.765 ;
     RECT  2.16 46.035 21.708 46.305 ;
     RECT  63.828 46.035 82.08 46.305 ;
     RECT  2.16 46.575 21.708 46.845 ;
     RECT  63.828 46.575 82.08 46.845 ;
     RECT  2.16 47.115 21.708 47.385 ;
     RECT  63.828 47.115 82.08 47.385 ;
     RECT  2.16 47.655 21.708 47.925 ;
     RECT  63.828 47.655 82.08 47.925 ;
     RECT  2.16 48.195 21.708 48.465 ;
     RECT  63.828 48.195 82.08 48.465 ;
     RECT  2.16 48.735 21.708 49.005 ;
     RECT  63.828 48.735 82.08 49.005 ;
     RECT  2.16 49.275 21.708 49.545 ;
     RECT  63.828 49.275 82.08 49.545 ;
     RECT  2.16 49.815 21.708 50.085 ;
     RECT  63.828 49.815 82.08 50.085 ;
     RECT  2.16 50.355 21.708 50.625 ;
     RECT  63.828 50.355 82.08 50.625 ;
     RECT  2.16 50.895 21.708 51.165 ;
     RECT  63.828 50.895 82.08 51.165 ;
     RECT  2.16 51.435 21.708 51.705 ;
     RECT  63.828 51.435 82.08 51.705 ;
     RECT  2.16 51.975 21.708 52.245 ;
     RECT  63.828 51.975 82.08 52.245 ;
     RECT  2.16 52.515 21.708 52.785 ;
     RECT  63.828 52.515 82.08 52.785 ;
     RECT  2.16 53.055 21.708 53.325 ;
     RECT  63.828 53.055 82.08 53.325 ;
     RECT  2.16 53.595 21.708 53.865 ;
     RECT  63.828 53.595 82.08 53.865 ;
     RECT  2.16 54.135 21.708 54.405 ;
     RECT  63.828 54.135 82.08 54.405 ;
     RECT  2.16 54.675 21.708 54.945 ;
     RECT  63.828 54.675 82.08 54.945 ;
     RECT  2.16 55.215 21.708 55.485 ;
     RECT  63.828 55.215 82.08 55.485 ;
     RECT  2.16 55.755 21.708 56.025 ;
     RECT  63.828 55.755 82.08 56.025 ;
     RECT  2.16 56.295 21.708 56.565 ;
     RECT  63.828 56.295 82.08 56.565 ;
     RECT  2.16 56.835 21.708 57.105 ;
     RECT  63.828 56.835 82.08 57.105 ;
     RECT  2.16 57.375 21.708 57.645 ;
     RECT  63.828 57.375 82.08 57.645 ;
     RECT  2.16 57.915 21.708 58.185 ;
     RECT  63.828 57.915 82.08 58.185 ;
     RECT  2.16 58.455 21.708 58.725 ;
     RECT  63.828 58.455 82.08 58.725 ;
     RECT  2.16 58.995 21.708 59.265 ;
     RECT  63.828 58.995 82.08 59.265 ;
     RECT  2.16 59.535 21.708 59.805 ;
     RECT  63.828 59.535 82.08 59.805 ;
     RECT  2.16 60.075 21.708 60.345 ;
     RECT  63.828 60.075 82.08 60.345 ;
     RECT  2.16 60.615 21.708 60.885 ;
     RECT  63.828 60.615 82.08 60.885 ;
     RECT  2.16 61.155 21.708 61.425 ;
     RECT  63.828 61.155 82.08 61.425 ;
     RECT  2.16 61.695 21.708 61.965 ;
     RECT  63.828 61.695 82.08 61.965 ;
     RECT  2.16 62.235 21.708 62.505 ;
     RECT  63.828 62.235 82.08 62.505 ;
     RECT  2.16 62.775 21.708 63.045 ;
     RECT  63.828 62.775 82.08 63.045 ;
     RECT  2.16 63.315 21.708 63.585 ;
     RECT  63.828 63.315 82.08 63.585 ;
     RECT  2.16 63.855 21.708 64.125 ;
     RECT  63.828 63.855 82.08 64.125 ;
     RECT  2.16 64.395 21.708 64.665 ;
     RECT  63.828 64.395 82.08 64.665 ;
     RECT  2.16 64.935 21.708 65.205 ;
     RECT  63.828 64.935 82.08 65.205 ;
     RECT  2.16 65.475 21.708 65.745 ;
     RECT  63.828 65.475 82.08 65.745 ;
     RECT  2.16 66.015 21.708 66.285 ;
     RECT  63.828 66.015 82.08 66.285 ;
     RECT  2.16 66.555 21.708 66.825 ;
     RECT  63.828 66.555 82.08 66.825 ;
     RECT  2.16 67.095 21.708 67.23 ;
     RECT  63.828 67.095 82.08 67.23 ;
     RECT  2.16 67.23 82.08 67.365 ;
     RECT  2.16 67.635 82.08 67.905 ;
     RECT  2.16 68.175 82.08 68.445 ;
     RECT  2.16 68.715 82.08 68.985 ;
    LAYER M1 ;
     RECT  23.76 2.16 61.8 65.112 ;
     RECT  2.16 2.151 21.708 67.221 ;
     RECT  63.828 2.151 82.08 67.221 ;
     RECT  2.16 67.221 82.08 69.129 ;
    LAYER M2 ;
     RECT  0.103 48.366 0.535 48.384 ;
     RECT  0.103 26.838 1.723 26.856 ;
     RECT  0.535 48.366 1.723 48.924 ;
     RECT  1.723 25.992 2.16 26.01 ;
     RECT  1.723 26.838 2.16 27.36 ;
     RECT  0.103 28.152 2.16 28.782 ;
     RECT  0.103 29.772 2.16 29.79 ;
     RECT  0.823 30.654 2.16 30.672 ;
     RECT  1.399 31.698 2.16 31.716 ;
     RECT  0.535 39.258 2.16 39.276 ;
     RECT  0.535 41.076 2.16 41.094 ;
     RECT  0.535 43.236 2.16 43.254 ;
     RECT  0.535 44.046 2.16 44.064 ;
     RECT  0.103 44.856 2.16 44.874 ;
     RECT  0.535 46.818 2.16 46.836 ;
     RECT  1.723 48.366 2.16 49.464 ;
     RECT  0.103 54.306 2.16 54.324 ;
     RECT  0.103 57.456 2.16 57.474 ;
     RECT  0.103 64.296 2.16 66.078 ;
     RECT  2.16 2.151 15.907 69.129 ;
     RECT  15.907 1.656 16.375 69.129 ;
     RECT  16.375 1.071 17.599 69.129 ;
     RECT  17.527 0.261 17.635 0.279 ;
     RECT  17.599 1.026 17.635 69.129 ;
     RECT  17.635 0.261 18.419 69.129 ;
     RECT  18.419 0.306 21.708 69.129 ;
     RECT  21.708 3.384 22.235 7.614 ;
     RECT  21.708 19.656 22.523 19.674 ;
     RECT  21.708 16.812 22.559 18.414 ;
     RECT  22.559 18.396 22.631 18.414 ;
     RECT  22.559 16.812 22.667 17.442 ;
     RECT  21.708 13.572 22.703 13.59 ;
     RECT  21.708 0.306 22.819 2.124 ;
     RECT  22.235 3.384 22.847 4.914 ;
     RECT  22.235 5.976 23.035 7.614 ;
     RECT  21.708 9.792 23.251 9.846 ;
     RECT  22.819 0.261 23.76 2.124 ;
     RECT  22.847 3.726 23.76 4.914 ;
     RECT  23.035 5.814 23.76 7.614 ;
     RECT  23.251 9.09 23.76 9.846 ;
     RECT  21.708 11.646 23.76 11.664 ;
     RECT  21.708 15.696 23.76 15.714 ;
     RECT  22.667 17.19 23.76 17.442 ;
     RECT  23.76 0.261 61.007 65.112 ;
     RECT  61.007 0.306 61.8 65.112 ;
     RECT  61.8 0.306 61.907 2.862 ;
     RECT  61.8 6.786 61.943 6.804 ;
     RECT  61.907 0.306 62.375 2.124 ;
     RECT  62.375 0.342 62.411 2.124 ;
     RECT  62.411 0.414 62.519 2.124 ;
     RECT  62.671 3.006 62.771 3.024 ;
     RECT  62.519 0.576 62.987 2.124 ;
     RECT  61.8 13.176 63.031 13.194 ;
     RECT  61.8 9.792 63.067 9.81 ;
     RECT  62.987 1.116 63.828 2.124 ;
     RECT  62.707 5.976 63.828 5.994 ;
     RECT  62.707 7.056 63.828 7.074 ;
     RECT  63.067 9.216 63.828 9.81 ;
     RECT  63.607 11.106 63.828 11.124 ;
     RECT  63.031 13.176 63.828 13.824 ;
     RECT  63.571 14.886 63.828 14.904 ;
     RECT  62.959 15.966 63.828 15.984 ;
     RECT  62.995 20.286 63.828 20.304 ;
     RECT  63.535 28.836 63.828 28.854 ;
     RECT  21.708 67.221 63.828 69.129 ;
     RECT  63.828 1.116 63.923 69.129 ;
     RECT  63.923 2.106 64.211 69.129 ;
     RECT  63.923 1.116 65.039 1.134 ;
     RECT  64.211 2.151 82.08 69.129 ;
    LAYER M3 ;
     RECT  18.396 0.256 18.414 0.301 ;
     RECT  17.532 0.256 17.55 0.337 ;
     RECT  18.396 0.301 18.954 0.337 ;
     RECT  62.352 0.301 62.37 0.337 ;
     RECT  62.352 0.337 62.406 0.373 ;
     RECT  62.136 0.373 62.406 0.409 ;
     RECT  22.824 0.256 22.842 0.427 ;
     RECT  62.136 0.409 62.514 0.427 ;
     RECT  62.136 0.427 62.766 0.526 ;
     RECT  62.064 0.526 62.766 0.571 ;
     RECT  60.984 0.256 61.002 0.599 ;
     RECT  22.536 0.427 22.842 0.796 ;
     RECT  58.716 0.751 58.734 0.796 ;
     RECT  62.064 0.571 62.982 0.913 ;
     RECT  62.028 0.913 62.982 0.949 ;
     RECT  13.896 0.955 13.914 1.003 ;
     RECT  22.536 0.796 23.382 1.049 ;
     RECT  58.716 0.796 58.806 1.049 ;
     RECT  13.644 1.003 13.914 1.051 ;
     RECT  22.536 1.049 23.31 1.094 ;
     RECT  17.532 0.337 18.954 1.147 ;
     RECT  20.088 0.811 20.106 1.147 ;
     RECT  22.536 1.094 23.274 1.291 ;
     RECT  20.088 1.147 20.178 1.387 ;
     RECT  19.872 1.387 20.178 1.435 ;
     RECT  17.532 1.147 19.026 1.483 ;
     RECT  19.8 1.435 20.178 1.483 ;
     RECT  17.532 1.483 20.178 1.627 ;
     RECT  16.38 1.066 16.398 1.651 ;
     RECT  15.084 0.907 15.102 1.675 ;
     RECT  15.912 1.651 16.398 1.687 ;
     RECT  65.016 1.111 65.034 1.915 ;
     RECT  64.98 1.915 65.034 2.011 ;
     RECT  66.024 1.963 66.042 2.011 ;
     RECT  15.912 1.687 16.578 2.101 ;
     RECT  17.424 1.627 20.178 2.101 ;
     RECT  63.9 1.525 63.918 2.101 ;
     RECT  63.9 2.101 64.206 2.107 ;
     RECT  64.98 2.011 66.042 2.107 ;
     RECT  13.536 1.051 13.914 2.143 ;
     RECT  22.5 1.291 23.274 2.16 ;
     RECT  58.716 1.049 58.734 2.16 ;
     RECT  61.56 0.949 62.982 2.16 ;
     RECT  15.084 1.675 15.174 2.191 ;
     RECT  15.912 2.101 20.178 2.191 ;
     RECT  20.988 0.523 21.006 2.191 ;
     RECT  63.9 2.107 66.042 2.219 ;
     RECT  15.084 2.191 20.178 2.251 ;
     RECT  20.988 2.191 21.114 2.251 ;
     RECT  15.084 2.251 21.114 2.285 ;
     RECT  63.9 2.219 65.862 2.291 ;
     RECT  2.415 2.143 2.505 2.413 ;
     RECT  7.815 2.143 7.905 2.413 ;
     RECT  67.215 2.143 67.305 2.413 ;
     RECT  72.615 2.143 72.705 2.413 ;
     RECT  78.015 2.143 78.105 2.413 ;
     RECT  15.912 2.285 21.114 2.641 ;
     RECT  63.9 2.291 65.502 2.861 ;
     RECT  15.912 2.641 21.294 2.923 ;
     RECT  15.912 2.923 21.582 3.115 ;
     RECT  65.016 2.861 65.502 3.299 ;
     RECT  65.016 3.299 65.322 3.437 ;
     RECT  15.912 3.115 21.654 4.109 ;
     RECT  15.084 2.285 15.102 4.531 ;
     RECT  15.948 4.109 21.654 4.555 ;
     RECT  22.5 2.16 62.982 4.555 ;
     RECT  13.215 2.143 13.914 4.765 ;
     RECT  13.176 4.765 13.914 4.801 ;
     RECT  15.084 4.531 15.138 4.801 ;
     RECT  12.348 1.099 12.366 4.919 ;
     RECT  13.176 4.801 15.138 5.035 ;
     RECT  15.948 4.555 62.982 5.035 ;
     RECT  13.176 5.035 62.982 5.071 ;
     RECT  13.14 5.071 62.982 5.189 ;
     RECT  11.376 5.071 11.394 5.227 ;
     RECT  13.14 5.189 21.366 5.611 ;
     RECT  22.212 5.189 62.982 5.611 ;
     RECT  22.212 5.611 63.054 5.707 ;
     RECT  63.9 2.861 64.206 5.707 ;
     RECT  65.016 3.437 65.034 5.707 ;
     RECT  22.212 5.707 64.206 5.803 ;
     RECT  65.016 5.707 65.106 5.803 ;
     RECT  11.304 5.227 11.394 5.845 ;
     RECT  12.888 5.611 21.366 5.845 ;
     RECT  12.744 5.845 21.366 5.881 ;
     RECT  11.16 5.845 11.394 5.885 ;
     RECT  22.212 5.803 65.106 6.179 ;
     RECT  22.5 6.179 65.106 6.283 ;
     RECT  11.484 6.385 11.502 6.461 ;
     RECT  22.5 6.283 65.358 6.539 ;
     RECT  12.24 5.881 21.366 6.655 ;
     RECT  22.5 6.539 65.322 7.079 ;
     RECT  7.815 2.413 8.097 7.231 ;
     RECT  7.815 7.231 8.622 7.357 ;
     RECT  9.792 7.231 9.81 7.357 ;
     RECT  5.364 7.195 5.382 7.429 ;
     RECT  7.815 7.357 9.81 7.429 ;
     RECT  5.256 7.429 5.706 7.501 ;
     RECT  6.444 7.465 6.462 7.501 ;
     RECT  7.488 7.429 9.81 7.501 ;
     RECT  10.836 7.123 10.854 7.501 ;
     RECT  5.256 7.501 6.462 7.591 ;
     RECT  7.236 7.501 10.854 7.591 ;
     RECT  5.256 7.591 10.854 7.663 ;
     RECT  12.024 6.655 21.366 7.675 ;
     RECT  2.415 2.413 2.697 7.699 ;
     RECT  5.04 7.663 10.854 7.699 ;
     RECT  2.415 7.699 3.402 7.771 ;
     RECT  4.356 7.699 10.854 7.771 ;
     RECT  11.988 7.675 21.366 7.771 ;
     RECT  2.415 7.771 11.142 7.861 ;
     RECT  11.916 7.771 21.366 7.861 ;
     RECT  22.5 7.079 65.214 7.889 ;
     RECT  2.415 7.861 21.366 8.429 ;
     RECT  2.415 8.429 10.026 8.437 ;
     RECT  10.764 8.429 21.366 8.851 ;
     RECT  2.376 8.437 10.026 8.969 ;
     RECT  10.764 8.851 21.474 8.969 ;
     RECT  2.415 8.969 10.026 9.163 ;
     RECT  10.764 8.969 21.366 9.163 ;
     RECT  2.415 9.163 21.366 10.121 ;
     RECT  2.415 10.121 4.554 10.939 ;
     RECT  5.292 10.121 21.366 10.939 ;
     RECT  2.415 10.939 21.366 11.227 ;
     RECT  22.5 7.889 65.034 11.281 ;
     RECT  2.34 11.227 21.366 11.471 ;
     RECT  22.5 11.281 65.106 11.741 ;
     RECT  2.415 11.471 21.366 12.217 ;
     RECT  2.376 12.217 21.366 12.361 ;
     RECT  2.376 12.361 21.51 12.479 ;
     RECT  22.5 11.741 65.034 13.099 ;
     RECT  22.5 13.099 65.322 13.199 ;
     RECT  62.964 13.199 65.322 13.289 ;
     RECT  62.964 13.289 65.034 13.829 ;
     RECT  62.964 13.829 64.782 14.827 ;
     RECT  2.376 12.479 21.366 14.909 ;
     RECT  62.964 14.827 64.998 14.909 ;
     RECT  2.376 14.909 20.61 14.945 ;
     RECT  2.376 14.945 20.574 15.053 ;
     RECT  2.376 15.053 20.502 15.961 ;
     RECT  62.964 14.909 64.782 15.989 ;
     RECT  2.376 15.961 20.574 16.141 ;
     RECT  21.348 14.909 21.366 16.141 ;
     RECT  2.376 16.141 21.366 16.541 ;
     RECT  63 15.989 64.782 16.799 ;
     RECT  65.556 16.555 65.574 16.799 ;
     RECT  63 16.799 64.638 16.973 ;
     RECT  22.5 13.199 61.8 17.447 ;
     RECT  2.415 16.541 21.366 17.491 ;
     RECT  2.415 17.491 21.474 17.609 ;
     RECT  2.415 17.609 21.366 17.879 ;
     RECT  2.415 17.879 20.61 18.091 ;
     RECT  22.5 17.447 22.626 18.419 ;
     RECT  21.348 17.879 21.366 18.571 ;
     RECT  21.348 18.571 21.582 18.797 ;
     RECT  2.376 18.091 20.61 18.811 ;
     RECT  21.348 18.797 21.438 18.811 ;
     RECT  2.376 18.811 21.438 19.075 ;
     RECT  22.5 18.419 22.518 19.679 ;
     RECT  63 16.973 64.134 20.309 ;
     RECT  65.124 19.963 65.142 20.309 ;
     RECT  63.54 20.309 64.134 20.425 ;
     RECT  63.54 20.425 64.206 20.477 ;
     RECT  2.34 19.075 21.438 21.005 ;
     RECT  2.415 21.005 21.438 21.569 ;
     RECT  63.54 20.477 64.134 21.695 ;
     RECT  2.415 21.569 21.366 22.795 ;
     RECT  2.34 22.795 21.366 24.431 ;
     RECT  2.415 24.431 21.366 25.789 ;
     RECT  2.34 25.789 21.366 25.987 ;
     RECT  1.728 25.987 21.366 26.237 ;
     RECT  0.108 26.824 0.126 26.861 ;
     RECT  2.34 26.237 21.366 27.337 ;
     RECT  1.728 27.337 21.366 27.533 ;
     RECT  0.108 28.123 0.126 28.787 ;
     RECT  64.476 28.507 64.494 28.831 ;
     RECT  63.54 21.695 63.558 28.859 ;
     RECT  64.476 28.831 64.638 28.949 ;
     RECT  65.376 21.667 65.394 28.949 ;
     RECT  2.415 27.533 21.366 29.129 ;
     RECT  2.415 29.129 21.186 29.371 ;
     RECT  2.304 29.371 21.186 29.489 ;
     RECT  2.304 29.489 20.754 29.525 ;
     RECT  2.304 29.525 20.466 29.561 ;
     RECT  2.304 29.561 20.178 29.831 ;
     RECT  2.304 29.831 2.862 29.867 ;
     RECT  3.816 29.831 20.178 29.867 ;
     RECT  2.415 29.867 2.862 30.029 ;
     RECT  3.996 29.867 20.178 30.029 ;
     RECT  3.996 30.029 19.746 30.065 ;
     RECT  0.108 29.767 0.126 30.077 ;
     RECT  2.415 30.029 2.754 30.677 ;
     RECT  4.572 30.065 16.038 30.811 ;
     RECT  16.812 30.065 19.746 30.811 ;
     RECT  4.14 30.811 19.746 30.991 ;
     RECT  4.14 30.991 19.962 31.145 ;
     RECT  12.132 31.145 19.962 31.181 ;
     RECT  12.132 31.181 19.746 31.217 ;
     RECT  4.14 31.145 11.394 31.325 ;
     RECT  0.828 30.649 0.846 31.693 ;
     RECT  4.212 31.325 11.394 31.867 ;
     RECT  12.132 31.217 19.422 31.867 ;
     RECT  4.212 31.867 19.422 32.099 ;
     RECT  4.212 32.099 19.278 32.155 ;
     RECT  3.708 32.155 19.278 32.495 ;
     RECT  3.708 32.495 16.542 32.531 ;
     RECT  15.3 32.531 16.542 32.567 ;
     RECT  17.892 32.495 19.278 32.729 ;
     RECT  15.3 32.567 15.966 32.801 ;
     RECT  3.708 32.531 14.49 32.999 ;
     RECT  3.708 32.999 14.058 33.143 ;
     RECT  15.3 32.801 15.498 33.449 ;
     RECT  3.708 33.143 14.022 33.845 ;
     RECT  19.944 33.835 19.962 33.881 ;
     RECT  20.448 33.931 20.466 34.079 ;
     RECT  21.564 33.925 21.582 34.157 ;
     RECT  0.828 31.693 1.422 34.411 ;
     RECT  3.96 33.845 14.022 34.501 ;
     RECT  0.108 34.411 1.422 34.541 ;
     RECT  3.96 34.501 14.454 34.619 ;
     RECT  15.48 33.449 15.498 34.651 ;
     RECT  3.96 34.619 13.986 34.735 ;
     RECT  3.492 34.735 13.986 34.763 ;
     RECT  14.796 34.651 15.498 34.781 ;
     RECT  3.492 34.763 13.914 34.889 ;
     RECT  3.492 34.889 13.77 35.033 ;
     RECT  17.892 32.729 18.897 35.069 ;
     RECT  15.48 34.781 15.498 35.537 ;
     RECT  3.492 35.033 13.662 36.275 ;
     RECT  2.415 30.677 2.697 36.715 ;
     RECT  2.304 36.715 2.697 36.779 ;
     RECT  2.415 36.779 2.697 36.859 ;
     RECT  3.492 36.275 13.497 36.859 ;
     RECT  2.415 36.859 13.497 36.887 ;
     RECT  2.415 36.887 10.134 36.923 ;
     RECT  10.872 36.887 13.497 36.923 ;
     RECT  2.415 36.923 9.414 37.049 ;
     RECT  10.872 36.923 12.186 37.049 ;
     RECT  10.872 37.049 11.322 37.121 ;
     RECT  12.924 36.923 13.497 37.193 ;
     RECT  3.492 37.049 9.414 37.319 ;
     RECT  12.96 37.193 13.497 37.769 ;
     RECT  10.44 37.675 10.458 38.201 ;
     RECT  2.415 37.049 2.697 39.181 ;
     RECT  3.492 37.319 9.198 39.181 ;
     RECT  0.828 34.541 1.422 39.253 ;
     RECT  2.415 39.181 9.198 39.281 ;
     RECT  3.492 39.281 9.198 39.353 ;
     RECT  0.54 39.253 1.422 39.389 ;
     RECT  6.192 39.353 9.198 39.749 ;
     RECT  6.444 39.749 9.198 40.441 ;
     RECT  6.444 40.441 9.306 40.559 ;
     RECT  0.828 39.389 1.422 41.071 ;
     RECT  3.492 39.353 5.382 41.071 ;
     RECT  6.444 40.559 9.198 41.071 ;
     RECT  2.415 39.281 2.697 41.107 ;
     RECT  3.492 41.071 9.198 41.107 ;
     RECT  2.415 41.107 9.198 41.369 ;
     RECT  0.54 41.071 1.422 41.755 ;
     RECT  0.108 41.755 1.422 41.885 ;
     RECT  2.415 41.369 2.697 42.601 ;
     RECT  2.304 42.601 2.697 42.653 ;
     RECT  3.492 41.369 9.198 43.061 ;
     RECT  0.828 41.885 1.422 43.231 ;
     RECT  6.228 43.061 9.198 43.645 ;
     RECT  3.492 43.061 5.382 43.951 ;
     RECT  6.228 43.645 9.306 44.069 ;
     RECT  3.42 43.951 5.382 44.113 ;
     RECT  6.228 44.069 9.198 44.113 ;
     RECT  2.415 42.653 2.697 44.419 ;
     RECT  3.42 44.113 9.198 44.419 ;
     RECT  2.415 44.419 9.198 44.477 ;
     RECT  0.54 43.231 1.422 44.827 ;
     RECT  0.108 44.827 1.422 44.879 ;
     RECT  3.6 44.477 9.198 46.741 ;
     RECT  0.828 44.879 1.422 46.813 ;
     RECT  2.415 44.477 2.697 46.921 ;
     RECT  3.528 46.741 9.198 46.921 ;
     RECT  0.54 46.813 1.422 46.973 ;
     RECT  2.415 46.921 9.198 47.309 ;
     RECT  3.708 47.309 9.198 47.921 ;
     RECT  0.828 46.973 1.422 48.331 ;
     RECT  0.108 48.331 1.422 48.389 ;
     RECT  0.54 48.389 1.422 49.085 ;
     RECT  5.004 47.921 9.198 49.315 ;
     RECT  0.828 49.085 1.422 49.441 ;
     RECT  2.415 47.309 2.697 49.441 ;
     RECT  3.708 47.921 4.23 49.477 ;
     RECT  5.004 49.315 9.306 49.477 ;
     RECT  3.708 49.477 9.306 49.513 ;
     RECT  3.636 49.513 9.306 49.621 ;
     RECT  3.42 49.621 9.306 49.739 ;
     RECT  0.828 49.441 2.697 49.757 ;
     RECT  2.415 49.757 2.697 49.981 ;
     RECT  3.42 49.739 9.198 49.981 ;
     RECT  2.415 49.981 9.198 50.045 ;
     RECT  0.828 49.757 1.422 50.347 ;
     RECT  3.492 50.045 9.198 50.423 ;
     RECT  3.492 50.423 4.23 50.459 ;
     RECT  0.108 50.347 1.422 50.477 ;
     RECT  4.968 50.423 9.198 50.729 ;
     RECT  4.968 50.729 8.262 50.855 ;
     RECT  4.968 50.855 5.346 50.927 ;
     RECT  6.3 50.855 8.262 51.197 ;
     RECT  6.408 51.197 8.262 51.503 ;
     RECT  0.828 50.477 1.422 51.739 ;
     RECT  0.108 51.739 1.422 51.869 ;
     RECT  6.516 51.503 8.262 51.979 ;
     RECT  9.072 50.729 9.198 51.979 ;
     RECT  6.516 51.979 9.198 52.051 ;
     RECT  6.516 52.051 9.486 52.169 ;
     RECT  9.072 52.169 9.486 52.277 ;
     RECT  2.415 50.045 2.697 52.411 ;
     RECT  3.708 50.459 4.23 52.411 ;
     RECT  5.004 50.927 5.346 52.411 ;
     RECT  3.708 52.411 5.346 52.555 ;
     RECT  2.268 52.411 2.697 52.589 ;
     RECT  3.672 52.555 5.346 52.591 ;
     RECT  3.42 52.591 5.346 52.753 ;
     RECT  2.415 52.589 2.697 52.789 ;
     RECT  3.42 52.753 5.418 52.789 ;
     RECT  2.415 52.789 5.418 52.829 ;
     RECT  3.708 52.829 5.418 53.179 ;
     RECT  3.708 53.179 5.778 53.221 ;
     RECT  6.516 52.169 8.226 53.221 ;
     RECT  3.708 53.221 8.226 53.563 ;
     RECT  9.072 52.277 9.198 53.563 ;
     RECT  3.708 53.563 9.198 53.591 ;
     RECT  0.828 51.869 1.422 53.947 ;
     RECT  3.708 53.591 8.406 54.131 ;
     RECT  5.004 54.131 8.406 54.203 ;
     RECT  0.108 53.947 1.422 54.329 ;
     RECT  6.192 54.203 8.406 54.337 ;
     RECT  9.18 53.591 9.198 54.337 ;
     RECT  6.192 54.337 9.198 54.401 ;
     RECT  6.84 54.401 9.198 54.679 ;
     RECT  6.84 54.679 9.45 54.743 ;
     RECT  9.288 54.743 9.45 54.869 ;
     RECT  9.288 54.869 9.306 54.905 ;
     RECT  3.708 54.131 4.23 55.291 ;
     RECT  0.828 54.329 1.422 55.339 ;
     RECT  0.108 55.339 1.422 55.469 ;
     RECT  3.42 55.291 4.23 55.525 ;
     RECT  5.004 54.203 5.346 55.525 ;
     RECT  3.42 55.525 5.346 55.651 ;
     RECT  2.415 52.829 2.697 55.819 ;
     RECT  3.42 55.651 5.742 55.819 ;
     RECT  2.415 55.819 5.742 55.859 ;
     RECT  3.744 55.859 5.742 55.921 ;
     RECT  3.744 55.921 5.922 56.291 ;
     RECT  5.004 56.291 5.922 56.371 ;
     RECT  6.912 54.743 8.406 56.497 ;
     RECT  5.004 56.371 6.066 56.525 ;
     RECT  6.84 56.497 8.406 56.597 ;
     RECT  2.415 55.859 2.697 56.731 ;
     RECT  2.304 56.731 2.697 56.768 ;
     RECT  5.004 56.525 5.67 56.768 ;
     RECT  5.004 56.768 5.562 56.795 ;
     RECT  6.84 56.597 8.262 57.037 ;
     RECT  6.408 57.037 8.262 57.101 ;
     RECT  0.828 55.469 1.422 57.451 ;
     RECT  0.108 57.451 1.422 57.488 ;
     RECT  9.288 57.415 9.306 57.569 ;
     RECT  6.84 57.101 8.262 57.577 ;
     RECT  3.744 56.291 4.23 57.685 ;
     RECT  6.84 57.577 8.838 57.749 ;
     RECT  8.82 57.749 8.838 57.875 ;
     RECT  2.415 56.768 2.697 57.991 ;
     RECT  3.636 57.685 4.23 57.991 ;
     RECT  5.004 56.795 5.346 57.991 ;
     RECT  2.415 57.991 2.79 58.081 ;
     RECT  2.268 58.081 2.79 58.123 ;
     RECT  3.636 57.991 5.346 58.123 ;
     RECT  2.268 58.123 5.346 58.157 ;
     RECT  2.415 58.157 5.346 58.379 ;
     RECT  2.415 58.379 3.222 58.451 ;
     RECT  3.96 58.379 5.346 58.523 ;
     RECT  3.996 58.523 5.346 59.197 ;
     RECT  3.996 59.197 5.706 59.233 ;
     RECT  6.84 57.749 8.097 59.233 ;
     RECT  3.996 59.233 8.097 59.459 ;
     RECT  3.996 59.459 5.814 59.729 ;
     RECT  3.996 59.729 5.13 59.801 ;
     RECT  3.996 59.801 4.878 59.809 ;
     RECT  3.528 59.809 4.878 59.837 ;
     RECT  3.528 59.837 4.41 60.305 ;
     RECT  3.528 60.305 3.546 60.413 ;
     RECT  4.392 60.305 4.41 61.133 ;
     RECT  5.472 61.579 5.49 61.591 ;
     RECT  5.472 61.591 5.814 61.619 ;
     RECT  0.828 57.488 1.422 61.901 ;
     RECT  5.796 61.619 5.814 62.141 ;
     RECT  0.828 61.901 0.846 62.621 ;
     RECT  6.84 59.459 8.097 63.259 ;
     RECT  6.12 63.259 8.097 63.319 ;
     RECT  5.544 63.319 8.097 63.545 ;
     RECT  6.84 63.545 8.097 63.581 ;
     RECT  6.84 63.581 6.858 63.815 ;
     RECT  23.76 17.447 61.8 65.112 ;
     RECT  0.108 64.219 0.126 66.125 ;
     RECT  24.207 67.213 24.297 67.483 ;
     RECT  29.607 67.213 29.697 67.483 ;
     RECT  35.007 67.213 35.097 67.483 ;
     RECT  40.407 67.213 40.497 67.483 ;
     RECT  45.807 67.213 45.897 67.483 ;
     RECT  51.207 67.213 51.297 67.483 ;
     RECT  56.607 67.213 56.697 67.483 ;
     RECT  62.007 67.213 62.097 67.483 ;
     RECT  2.415 58.451 2.697 68.867 ;
     RECT  7.815 63.581 8.097 68.867 ;
     RECT  13.215 37.769 13.497 68.867 ;
     RECT  18.615 35.069 18.897 68.867 ;
     RECT  24.015 67.483 24.297 68.867 ;
     RECT  29.415 67.483 29.697 68.867 ;
     RECT  34.815 67.483 35.097 68.867 ;
     RECT  40.215 67.483 40.497 68.867 ;
     RECT  45.615 67.483 45.897 68.867 ;
     RECT  51.015 67.483 51.297 68.867 ;
     RECT  56.415 67.483 56.697 68.867 ;
     RECT  61.815 67.483 62.097 68.867 ;
     RECT  67.215 2.413 67.497 68.867 ;
     RECT  72.615 2.413 72.897 68.867 ;
     RECT  78.015 2.413 78.297 68.867 ;
     RECT  2.415 68.867 2.505 69.137 ;
     RECT  7.815 68.867 7.905 69.137 ;
     RECT  13.215 68.867 13.305 69.137 ;
     RECT  18.615 68.867 18.705 69.137 ;
     RECT  24.015 68.867 24.105 69.137 ;
     RECT  29.415 68.867 29.505 69.137 ;
     RECT  34.815 68.867 34.905 69.137 ;
     RECT  40.215 68.867 40.305 69.137 ;
     RECT  45.615 68.867 45.705 69.137 ;
     RECT  51.015 68.867 51.105 69.137 ;
     RECT  56.415 68.867 56.505 69.137 ;
     RECT  61.815 68.867 61.905 69.137 ;
     RECT  67.215 68.867 67.305 69.137 ;
     RECT  72.615 68.867 72.705 69.137 ;
     RECT  78.015 68.867 78.105 69.137 ;
    LAYER M4 ;
     RECT  0.084 26.208 0.137 26.232 ;
     RECT  0.06 26.232 0.137 26.832 ;
     RECT  0.084 26.832 0.137 26.856 ;
     RECT  0.06 26.856 0.137 27.504 ;
     RECT  0.084 27.504 0.137 27.528 ;
     RECT  0.06 27.528 0.137 28.128 ;
     RECT  0.084 28.128 0.137 28.152 ;
     RECT  0.06 28.152 0.137 28.752 ;
     RECT  0.084 28.752 0.137 28.776 ;
     RECT  0.06 28.776 0.137 29.376 ;
     RECT  0.084 29.376 0.137 29.4 ;
     RECT  0.06 29.4 0.137 30.048 ;
     RECT  0.084 30.048 0.137 30.072 ;
     RECT  0.097 34.416 0.137 34.536 ;
     RECT  0.084 40.368 0.137 40.392 ;
     RECT  0.06 40.392 0.137 41.136 ;
     RECT  0.084 41.136 0.137 41.16 ;
     RECT  0.06 41.16 0.137 41.856 ;
     RECT  0.084 41.856 0.137 41.88 ;
     RECT  0.06 41.88 0.137 42.624 ;
     RECT  0.084 42.624 0.137 42.648 ;
     RECT  0.06 42.648 0.137 43.344 ;
     RECT  0.084 43.344 0.137 43.368 ;
     RECT  0.06 43.368 0.137 44.112 ;
     RECT  0.084 44.112 0.137 44.136 ;
     RECT  0.06 44.136 0.137 44.832 ;
     RECT  0.084 44.832 0.137 44.856 ;
     RECT  0.06 44.856 0.137 45.552 ;
     RECT  0.084 45.552 0.137 45.576 ;
     RECT  0.06 45.576 0.137 46.224 ;
     RECT  0.084 46.224 0.137 46.248 ;
     RECT  0.06 46.248 0.137 46.944 ;
     RECT  0.084 46.944 0.137 46.968 ;
     RECT  0.06 46.968 0.137 47.616 ;
     RECT  0.084 47.616 0.137 47.64 ;
     RECT  0.06 47.64 0.137 48.336 ;
     RECT  0.084 48.336 0.137 48.36 ;
     RECT  0.06 48.36 0.137 49.056 ;
     RECT  0.084 49.056 0.137 49.08 ;
     RECT  0.06 49.08 0.137 49.728 ;
     RECT  0.084 49.728 0.137 49.752 ;
     RECT  0.06 49.752 0.137 50.448 ;
     RECT  0.084 50.448 0.137 50.472 ;
     RECT  0.06 50.472 0.137 51.12 ;
     RECT  0.084 51.12 0.137 51.144 ;
     RECT  0.06 51.144 0.137 51.84 ;
     RECT  0.084 51.84 0.137 51.864 ;
     RECT  0.06 51.864 0.137 52.56 ;
     RECT  0.084 52.56 0.137 52.584 ;
     RECT  0.06 52.584 0.137 53.232 ;
     RECT  0.084 53.232 0.137 53.256 ;
     RECT  0.06 53.256 0.137 53.952 ;
     RECT  0.084 53.952 0.137 53.976 ;
     RECT  0.06 53.976 0.137 54.624 ;
     RECT  0.084 54.624 0.137 54.648 ;
     RECT  0.06 54.648 0.137 55.344 ;
     RECT  0.084 55.344 0.137 55.368 ;
     RECT  0.06 55.368 0.137 56.016 ;
     RECT  0.084 56.016 0.137 56.04 ;
     RECT  0.06 56.04 0.137 56.736 ;
     RECT  0.084 56.736 0.137 56.76 ;
     RECT  0.06 56.76 0.137 57.456 ;
     RECT  0.084 57.456 0.137 57.48 ;
     RECT  0.06 57.48 0.137 58.128 ;
     RECT  0.084 58.128 0.137 58.152 ;
     RECT  0.084 60.384 0.137 60.408 ;
     RECT  0.06 60.408 0.137 61.104 ;
     RECT  0.084 61.104 0.137 61.128 ;
     RECT  0.06 61.128 0.137 61.872 ;
     RECT  0.084 61.872 0.137 61.896 ;
     RECT  0.06 61.896 0.137 62.592 ;
     RECT  0.084 62.592 0.137 62.616 ;
     RECT  0.06 62.616 0.137 63.504 ;
     RECT  0.084 63.504 0.137 63.528 ;
     RECT  0.06 63.528 0.137 64.224 ;
     RECT  0.084 64.224 0.137 64.248 ;
     RECT  0.06 64.248 0.137 64.752 ;
     RECT  0.084 64.752 0.137 64.776 ;
     RECT  0.06 64.776 0.137 65.376 ;
     RECT  0.084 65.376 0.137 65.4 ;
     RECT  0.06 65.4 0.137 66.096 ;
     RECT  0.084 66.096 0.137 66.12 ;
     RECT  0.137 40.368 0.569 44.136 ;
     RECT  0.137 45.552 0.569 47.64 ;
     RECT  0.137 49.056 0.569 53.256 ;
     RECT  0.137 60.384 0.857 63.528 ;
     RECT  0.857 60.384 1.433 61.896 ;
     RECT  2.329 11.232 2.408 11.256 ;
     RECT  2.365 12.24 2.408 12.264 ;
     RECT  2.293 16.512 2.408 16.536 ;
     RECT  2.293 17.616 2.408 18.12 ;
     RECT  2.293 20.976 2.408 21.816 ;
     RECT  2.285 22.8 2.408 22.824 ;
     RECT  0.137 26.208 2.408 26.232 ;
     RECT  0.137 27.504 2.408 27.528 ;
     RECT  0.137 29.376 2.408 29.4 ;
     RECT  0.137 34.416 2.408 34.44 ;
     RECT  0.569 40.368 2.408 40.392 ;
     RECT  0.569 41.76 2.408 42.648 ;
     RECT  0.569 45.552 2.408 46.248 ;
     RECT  0.569 47.616 2.408 47.64 ;
     RECT  0.569 49.728 2.408 53.256 ;
     RECT  0.137 54.624 2.408 56.76 ;
     RECT  0.137 58.128 2.408 58.152 ;
     RECT  1.433 60.384 2.408 61.128 ;
     RECT  0.857 63.504 2.408 63.528 ;
     RECT  2.408 2.148 2.512 69.132 ;
     RECT  2.512 2.418 2.704 68.862 ;
     RECT  2.704 28.464 2.819 29.784 ;
     RECT  2.704 58.128 3.277 58.152 ;
     RECT  2.819 28.464 3.485 28.536 ;
     RECT  2.704 50.016 3.521 51.768 ;
     RECT  2.704 54.624 3.557 56.76 ;
     RECT  2.704 60.384 3.557 61.128 ;
     RECT  2.704 44.208 3.593 44.472 ;
     RECT  2.704 32.256 3.692 32.28 ;
     RECT  3.692 32.16 3.733 32.28 ;
     RECT  2.704 45.552 3.733 46.248 ;
     RECT  2.704 47.232 3.733 47.64 ;
     RECT  2.704 24.336 3.769 24.984 ;
     RECT  2.704 21.792 3.841 21.816 ;
     RECT  2.704 11.232 3.877 12.264 ;
     RECT  2.704 16.032 3.877 16.056 ;
     RECT  3.877 15.984 3.913 16.056 ;
     RECT  2.704 17.04 3.913 17.64 ;
     RECT  2.704 20.16 3.985 20.76 ;
     RECT  3.841 21.792 3.985 22.248 ;
     RECT  3.985 20.16 4.021 22.248 ;
     RECT  2.704 59.232 4.025 59.256 ;
     RECT  3.913 15.984 4.057 17.64 ;
     RECT  2.704 38.112 4.061 38.136 ;
     RECT  4.021 19.344 4.067 22.248 ;
     RECT  3.733 31.296 4.129 32.28 ;
     RECT  3.877 11.184 4.169 12.264 ;
     RECT  4.067 20.736 4.169 22.248 ;
     RECT  2.704 36.768 4.268 37.032 ;
     RECT  2.704 40.368 4.309 41.784 ;
     RECT  4.268 36.432 4.355 37.032 ;
     RECT  4.268 38.16 4.355 38.184 ;
     RECT  4.309 39.552 4.355 41.88 ;
     RECT  3.769 24.336 4.385 25.032 ;
     RECT  3.733 45.552 4.385 47.64 ;
     RECT  3.557 61.104 4.421 61.128 ;
     RECT  4.169 11.184 4.489 12.072 ;
     RECT  4.309 13.344 4.493 13.368 ;
     RECT  4.057 15.84 4.501 17.64 ;
     RECT  3.485 28.512 4.525 28.536 ;
     RECT  4.489 10.944 4.529 12.072 ;
     RECT  4.169 20.976 4.529 22.248 ;
     RECT  4.529 21.072 4.549 22.248 ;
     RECT  3.593 44.448 4.549 44.472 ;
     RECT  4.385 45.552 4.549 47.352 ;
     RECT  2.704 52.8 4.549 53.256 ;
     RECT  2.704 34.512 4.561 34.536 ;
     RECT  4.549 21.072 4.595 22.824 ;
     RECT  4.549 44.448 4.595 47.352 ;
     RECT  4.549 52.8 4.595 53.592 ;
     RECT  4.525 13.104 4.637 13.128 ;
     RECT  4.525 28.464 4.669 28.536 ;
     RECT  4.529 10.944 4.673 11.208 ;
     RECT  4.669 27.84 4.693 28.536 ;
     RECT  2.704 26.112 4.741 26.136 ;
     RECT  4.693 27.792 4.741 28.536 ;
     RECT  2.819 29.76 4.813 29.784 ;
     RECT  4.129 30.816 4.813 32.28 ;
     RECT  3.521 50.016 4.813 50.04 ;
     RECT  4.595 53.568 4.813 53.592 ;
     RECT  3.557 54.624 4.813 54.648 ;
     RECT  4.741 26.112 4.825 28.536 ;
     RECT  4.355 41.856 4.849 41.88 ;
     RECT  4.837 43.056 4.849 43.08 ;
     RECT  4.813 29.76 4.853 32.28 ;
     RECT  4.595 47.328 4.853 47.352 ;
     RECT  4.813 49.872 4.853 50.04 ;
     RECT  4.595 44.448 4.883 46.344 ;
     RECT  4.849 41.856 4.889 43.08 ;
     RECT  4.813 53.568 4.897 54.648 ;
     RECT  3.557 55.824 4.917 56.76 ;
     RECT  4.501 15.84 4.921 17.976 ;
     RECT  4.883 45.12 4.924 46.344 ;
     RECT  4.921 15.36 4.957 17.976 ;
     RECT  4.067 19.344 4.997 19.368 ;
     RECT  4.957 14.784 5.033 17.976 ;
     RECT  4.849 59.808 5.123 59.832 ;
     RECT  4.561 34.512 5.125 34.872 ;
     RECT  4.595 22.08 5.137 22.824 ;
     RECT  5.125 33.84 5.171 34.872 ;
     RECT  4.385 25.008 5.177 25.032 ;
     RECT  4.924 45.552 5.177 46.344 ;
     RECT  3.521 51.12 5.177 51.768 ;
     RECT  4.889 42.144 5.245 43.08 ;
     RECT  5.245 42.144 5.285 43.176 ;
     RECT  4.595 21.072 5.393 21.096 ;
     RECT  5.077 61.632 5.461 61.656 ;
     RECT  2.704 7.92 5.641 7.944 ;
     RECT  5.137 22.08 5.641 23.016 ;
     RECT  5.605 25.104 5.653 25.128 ;
     RECT  4.825 26.112 5.653 26.856 ;
     RECT  5.641 7.92 5.681 8.04 ;
     RECT  4.825 27.84 5.681 28.536 ;
     RECT  4.917 56.736 5.681 56.76 ;
     RECT  2.704 63.504 5.681 63.528 ;
     RECT  4.897 53.568 5.708 53.592 ;
     RECT  5.681 28.128 5.717 28.536 ;
     RECT  5.641 22.08 5.785 23.112 ;
     RECT  5.461 61.584 5.785 61.656 ;
     RECT  5.285 42.816 5.795 43.176 ;
     RECT  5.708 53.184 5.795 53.592 ;
     RECT  5.785 61.584 5.795 62.136 ;
     RECT  5.795 61.632 5.825 62.136 ;
     RECT  5.785 21.12 5.869 23.112 ;
     RECT  5.033 17.952 5.941 17.976 ;
     RECT  5.033 14.784 6.005 16.728 ;
     RECT  4.673 10.944 6.109 10.968 ;
     RECT  5.825 62.112 6.131 62.136 ;
     RECT  6.001 19.776 6.145 19.8 ;
     RECT  5.171 33.84 6.145 33.864 ;
     RECT  5.171 34.848 6.145 34.872 ;
     RECT  6.065 63.264 6.149 63.288 ;
     RECT  6.005 14.784 6.181 16.152 ;
     RECT  6.145 19.584 6.181 19.8 ;
     RECT  6.145 33.84 6.217 34.872 ;
     RECT  6.217 33.84 6.253 35.208 ;
     RECT  6.109 10.224 6.289 10.968 ;
     RECT  5.681 8.016 6.361 8.04 ;
     RECT  5.653 25.104 6.361 26.856 ;
     RECT  6.181 19.584 6.365 19.944 ;
     RECT  4.853 49.872 6.373 49.896 ;
     RECT  5.177 51.744 6.38 51.768 ;
     RECT  5.795 53.232 6.38 53.592 ;
     RECT  4.897 54.624 6.38 54.648 ;
     RECT  4.853 30.24 6.397 32.28 ;
     RECT  6.373 49.344 6.397 49.896 ;
     RECT  4.355 39.552 6.421 40.392 ;
     RECT  6.38 51.456 6.421 51.768 ;
     RECT  5.795 42.816 6.437 43.032 ;
     RECT  6.421 51.456 6.467 52.056 ;
     RECT  5.941 17.952 6.469 18.072 ;
     RECT  6.397 49.248 6.481 49.896 ;
     RECT  6.421 39.552 6.501 40.728 ;
     RECT  6.38 53.232 6.508 54.648 ;
     RECT  6.469 17.904 6.509 18.072 ;
     RECT  6.365 19.584 6.509 19.8 ;
     RECT  6.361 8.016 6.541 9.096 ;
     RECT  6.509 19.584 6.577 19.608 ;
     RECT  6.541 8.016 6.685 9.144 ;
     RECT  6.289 10.224 6.685 11.544 ;
     RECT  6.397 29.664 6.689 32.28 ;
     RECT  5.717 28.512 6.721 28.536 ;
     RECT  6.689 29.664 6.721 31.896 ;
     RECT  6.181 14.16 6.797 16.152 ;
     RECT  6.253 33.84 7.009 35.304 ;
     RECT  5.869 21.552 7.117 23.112 ;
     RECT  7.117 21.504 7.189 23.112 ;
     RECT  6.361 24.144 7.189 26.856 ;
     RECT  6.509 17.904 7.585 17.928 ;
     RECT  6.577 19.248 7.585 19.608 ;
     RECT  6.721 28.512 7.585 31.896 ;
     RECT  6.797 14.64 7.669 16.152 ;
     RECT  7.585 17.136 7.669 17.928 ;
     RECT  6.685 8.016 7.808 11.544 ;
     RECT  7.649 12.576 7.808 12.6 ;
     RECT  7.669 14.64 7.808 17.928 ;
     RECT  7.585 19.248 7.808 19.896 ;
     RECT  7.189 21.504 7.808 26.856 ;
     RECT  7.585 28.416 7.808 31.896 ;
     RECT  7.009 33.648 7.808 35.304 ;
     RECT  7.513 37.056 7.808 37.08 ;
     RECT  6.501 40.368 7.808 40.728 ;
     RECT  6.437 43.008 7.808 43.032 ;
     RECT  7.477 44.448 7.808 44.472 ;
     RECT  5.177 45.696 7.808 46.344 ;
     RECT  6.481 49.872 7.808 49.896 ;
     RECT  6.467 51.744 7.808 52.056 ;
     RECT  6.508 54.192 7.808 54.648 ;
     RECT  6.397 57.072 7.808 57.096 ;
     RECT  7.808 2.148 7.912 69.132 ;
     RECT  7.912 2.418 8.104 68.862 ;
     RECT  8.104 17.904 8.129 20.088 ;
     RECT  8.129 17.904 8.201 18.984 ;
     RECT  8.104 54.192 8.243 54.744 ;
     RECT  8.104 57.072 8.243 57.624 ;
     RECT  8.104 7.92 8.339 9.24 ;
     RECT  8.129 20.064 8.525 20.088 ;
     RECT  8.104 29.856 8.525 31.8 ;
     RECT  8.104 21.072 8.633 28.44 ;
     RECT  8.104 33.648 8.705 37.08 ;
     RECT  8.339 7.92 8.813 7.944 ;
     RECT  8.104 10.32 8.849 10.968 ;
     RECT  8.104 15.072 8.849 16.392 ;
     RECT  8.705 33.84 8.849 37.08 ;
     RECT  8.633 21.072 8.957 25.752 ;
     RECT  8.957 21.072 8.993 25.272 ;
     RECT  8.993 21.072 9.029 23.208 ;
     RECT  8.849 33.84 9.1 36.888 ;
     RECT  8.633 26.736 9.109 28.44 ;
     RECT  8.525 29.856 9.109 30.36 ;
     RECT  9.109 26.736 9.155 30.36 ;
     RECT  9.155 26.736 9.173 29.064 ;
     RECT  8.339 8.976 9.245 9.24 ;
     RECT  9.1 36.48 9.245 36.888 ;
     RECT  8.993 24.288 9.281 25.272 ;
     RECT  9.173 26.736 9.281 27.864 ;
     RECT  9.155 30.192 9.299 30.36 ;
     RECT  8.849 15.456 9.349 16.392 ;
     RECT  8.201 17.904 9.349 17.928 ;
     RECT  9.281 24.576 9.353 25.272 ;
     RECT  9.281 27.6 9.353 27.864 ;
     RECT  8.104 43.008 9.395 43.032 ;
     RECT  8.201 18.96 9.461 18.984 ;
     RECT  9.173 29.04 9.461 29.064 ;
     RECT  9.349 15.456 9.533 17.928 ;
     RECT  9.353 27.648 9.533 27.864 ;
     RECT  8.525 31.392 9.589 31.8 ;
     RECT  9.313 20.112 9.637 20.136 ;
     RECT  9.589 31.392 9.637 32.76 ;
     RECT  9.637 31.344 9.677 32.76 ;
     RECT  9.637 19.248 9.749 20.136 ;
     RECT  8.104 13.44 9.781 13.464 ;
     RECT  9.1 33.84 9.781 35.352 ;
     RECT  9.781 13.44 9.785 14.136 ;
     RECT  9.029 21.168 9.821 23.208 ;
     RECT  9.821 21.216 9.929 23.208 ;
     RECT  9.749 19.248 10.109 19.8 ;
     RECT  10.141 12.24 10.261 12.264 ;
     RECT  9.929 21.36 10.285 23.208 ;
     RECT  9.353 24.72 10.325 25.272 ;
     RECT  9.785 14.112 10.357 14.136 ;
     RECT  9.533 15.456 10.357 16.392 ;
     RECT  9.245 9.216 10.393 9.24 ;
     RECT  8.849 10.32 10.393 10.872 ;
     RECT  10.357 14.112 10.403 16.392 ;
     RECT  10.325 24.96 10.429 25.272 ;
     RECT  10.357 26.544 10.429 26.568 ;
     RECT  9.533 27.648 10.429 27.672 ;
     RECT  9.299 30.336 10.429 30.36 ;
     RECT  9.349 38.16 10.429 38.184 ;
     RECT  10.403 14.784 10.461 16.392 ;
     RECT  10.429 30.24 10.465 30.36 ;
     RECT  9.677 31.344 10.465 32.28 ;
     RECT  10.393 9.216 10.469 10.872 ;
     RECT  10.429 37.68 10.469 38.184 ;
     RECT  10.429 24.96 10.501 25.368 ;
     RECT  10.261 12.24 10.505 12.888 ;
     RECT  10.109 19.248 10.505 19.368 ;
     RECT  10.469 9.216 10.537 9.912 ;
     RECT  10.501 24.96 10.537 25.464 ;
     RECT  10.429 26.544 10.537 27.672 ;
     RECT  10.505 12.288 10.685 12.888 ;
     RECT  10.537 24.96 10.793 27.672 ;
     RECT  10.505 19.344 10.829 19.368 ;
     RECT  10.793 27.648 10.861 27.672 ;
     RECT  10.465 30.24 10.885 32.28 ;
     RECT  9.781 33.36 10.885 35.352 ;
     RECT  10.885 30.24 10.925 35.352 ;
     RECT  9.245 36.48 10.925 36.504 ;
     RECT  10.925 30.24 10.933 36.504 ;
     RECT  10.861 27.648 10.973 27.96 ;
     RECT  10.461 14.784 11.009 15.528 ;
     RECT  10.933 29.52 11.009 36.504 ;
     RECT  11.009 29.52 11.041 35.016 ;
     RECT  11.077 5.856 11.189 6.456 ;
     RECT  10.537 9.168 11.257 9.912 ;
     RECT  10.285 21.36 11.329 23.688 ;
     RECT  11.041 29.184 11.333 35.016 ;
     RECT  9.533 17.904 11.401 17.928 ;
     RECT  11.257 8.928 11.405 9.912 ;
     RECT  10.685 12.288 11.581 12.36 ;
     RECT  11.009 36.48 11.657 36.504 ;
     RECT  11.329 21.216 11.689 23.688 ;
     RECT  10.793 24.96 11.689 26.376 ;
     RECT  11.401 17.088 11.833 17.928 ;
     RECT  10.973 27.936 11.873 27.96 ;
     RECT  11.833 16.944 11.909 17.928 ;
     RECT  11.581 11.52 11.941 12.36 ;
     RECT  11.941 11.52 11.987 13.32 ;
     RECT  11.987 11.52 12.017 12.312 ;
     RECT  11.333 29.184 12.017 30.744 ;
     RECT  11.909 16.944 12.325 16.968 ;
     RECT  11.405 8.928 12.373 9.336 ;
     RECT  11.987 13.296 12.373 13.32 ;
     RECT  11.689 21.216 12.445 26.376 ;
     RECT  12.445 21.216 12.481 26.616 ;
     RECT  12.445 27.984 12.481 28.008 ;
     RECT  12.017 29.184 12.481 30.36 ;
     RECT  11.977 7.68 12.661 7.704 ;
     RECT  12.373 8.928 12.661 10.104 ;
     RECT  11.293 5.232 12.877 5.256 ;
     RECT  11.189 6.432 12.877 6.456 ;
     RECT  12.325 16.56 12.877 16.968 ;
     RECT  12.877 16.56 12.985 17.784 ;
     RECT  12.481 27.984 13.021 30.36 ;
     RECT  12.017 11.52 13.093 12.216 ;
     RECT  12.373 13.296 13.093 13.416 ;
     RECT  11.333 31.872 13.093 35.016 ;
     RECT  12.877 5.232 13.208 6.456 ;
     RECT  12.661 7.68 13.208 10.104 ;
     RECT  13.093 11.52 13.208 13.416 ;
     RECT  11.009 14.928 13.208 15.528 ;
     RECT  12.985 16.56 13.208 17.88 ;
     RECT  12.481 21.216 13.208 26.808 ;
     RECT  13.021 27.888 13.208 30.6 ;
     RECT  13.093 31.68 13.208 35.016 ;
     RECT  10.469 37.68 13.208 37.704 ;
     RECT  13.208 2.148 13.312 69.132 ;
     RECT  13.312 2.418 13.504 68.862 ;
     RECT  12.337 1.104 13.525 1.128 ;
     RECT  13.525 1.056 13.633 1.128 ;
     RECT  13.504 27.648 13.667 35.016 ;
     RECT  13.504 16.32 13.715 18.648 ;
     RECT  13.667 27.648 13.753 32.52 ;
     RECT  13.504 20.064 13.763 25.08 ;
     RECT  13.753 27.648 13.859 29.304 ;
     RECT  13.633 1.008 13.885 1.128 ;
     RECT  13.504 11.28 13.925 11.832 ;
     RECT  13.753 30.336 14.003 32.52 ;
     RECT  13.859 27.888 14.033 29.304 ;
     RECT  14.033 27.888 14.195 29.016 ;
     RECT  13.504 26.208 14.213 26.568 ;
     RECT  13.763 20.064 14.285 25.032 ;
     RECT  13.715 16.32 14.393 18.504 ;
     RECT  14.285 20.064 14.465 24.648 ;
     RECT  14.465 24.432 14.483 24.648 ;
     RECT  13.925 11.52 14.573 11.832 ;
     RECT  13.504 5.232 14.605 8.04 ;
     RECT  13.504 13.056 14.641 13.848 ;
     RECT  13.504 14.928 14.641 14.952 ;
     RECT  14.465 20.064 14.645 23.352 ;
     RECT  14.641 13.056 14.717 14.952 ;
     RECT  14.717 14.688 14.785 14.952 ;
     RECT  14.393 16.32 14.785 18.216 ;
     RECT  14.605 5.04 14.789 8.04 ;
     RECT  14.717 13.056 14.789 13.656 ;
     RECT  14.789 5.04 14.821 7.128 ;
     RECT  13.504 9.84 14.893 10.104 ;
     RECT  14.195 28.752 14.897 29.016 ;
     RECT  14.789 13.632 14.933 13.656 ;
     RECT  14.785 14.688 14.933 18.216 ;
     RECT  14.003 32.208 15.005 32.52 ;
     RECT  13.885 0.96 15.073 1.128 ;
     RECT  14.645 20.064 15.113 23.304 ;
     RECT  15.073 0.912 15.145 1.128 ;
     RECT  14.213 26.208 15.181 26.52 ;
     RECT  14.483 24.48 15.253 24.648 ;
     RECT  15.181 26.208 15.253 26.568 ;
     RECT  14.821 4.944 15.329 7.128 ;
     RECT  15.145 0.912 15.349 1.704 ;
     RECT  14.897 28.944 15.349 29.016 ;
     RECT  13.667 33.84 15.395 35.016 ;
     RECT  14.893 9.264 15.397 10.104 ;
     RECT  15.349 28.944 15.436 29.352 ;
     RECT  15.349 0.912 15.437 2.28 ;
     RECT  15.005 32.208 15.491 32.424 ;
     RECT  15.436 28.944 15.532 29.256 ;
     RECT  15.445 3.072 15.541 3.096 ;
     RECT  15.397 9.264 15.541 10.296 ;
     RECT  15.469 19.824 15.577 19.848 ;
     RECT  15.532 28.944 15.587 29.208 ;
     RECT  15.541 9.072 15.793 10.296 ;
     RECT  15.253 24.48 15.797 26.568 ;
     RECT  15.113 21.408 15.869 23.304 ;
     RECT  15.797 24.48 15.905 26.52 ;
     RECT  15.329 4.944 15.937 6.888 ;
     RECT  15.869 22.848 15.937 23.304 ;
     RECT  15.587 28.944 15.973 29.016 ;
     RECT  15.905 25.104 15.977 26.52 ;
     RECT  14.857 12.528 16.013 12.552 ;
     RECT  15.793 9.072 16.049 10.392 ;
     RECT  15.541 3.072 16.153 3.576 ;
     RECT  15.937 4.752 16.153 6.888 ;
     RECT  15.869 21.408 16.193 21.432 ;
     RECT  15.605 18.24 16.261 18.264 ;
     RECT  15.577 19.536 16.261 19.848 ;
     RECT  15.937 22.848 16.337 23.88 ;
     RECT  16.261 18.24 16.373 19.848 ;
     RECT  16.373 18.24 16.405 18.552 ;
     RECT  15.491 32.4 16.481 32.424 ;
     RECT  16.049 9.072 16.517 10.296 ;
     RECT  16.337 22.848 16.553 23.352 ;
     RECT  16.553 23.04 16.589 23.352 ;
     RECT  14.573 11.52 16.595 11.544 ;
     RECT  15.973 28.896 16.621 29.016 ;
     RECT  14.003 30.336 16.621 30.936 ;
     RECT  16.153 3.072 16.657 6.888 ;
     RECT  14.933 14.688 16.697 17.112 ;
     RECT  16.697 14.688 16.733 15.048 ;
     RECT  16.405 18.144 16.805 18.552 ;
     RECT  16.657 3.072 16.837 6.984 ;
     RECT  16.517 9.072 16.909 10.104 ;
     RECT  16.621 28.896 16.913 30.936 ;
     RECT  16.697 16.08 16.985 17.112 ;
     RECT  15.977 26.016 16.985 26.52 ;
     RECT  16.373 19.536 17.057 19.848 ;
     RECT  16.909 8.496 17.123 10.104 ;
     RECT  16.733 14.928 17.129 15.048 ;
     RECT  17.057 19.824 17.129 19.848 ;
     RECT  17.053 28.704 17.197 28.728 ;
     RECT  17.197 28.512 17.201 28.728 ;
     RECT  16.589 23.28 17.237 23.352 ;
     RECT  17.377 21.168 17.485 21.192 ;
     RECT  17.449 25.248 17.509 25.272 ;
     RECT  16.985 16.416 17.521 17.112 ;
     RECT  16.985 26.304 17.605 26.52 ;
     RECT  17.123 8.496 17.629 8.52 ;
     RECT  17.509 25.104 17.633 25.272 ;
     RECT  16.913 29.76 17.633 30.936 ;
     RECT  16.729 12.24 17.737 12.504 ;
     RECT  15.437 0.912 17.773 1.704 ;
     RECT  16.837 3.024 17.773 6.984 ;
     RECT  16.805 18.432 18.025 18.552 ;
     RECT  17.629 8.448 18.061 8.52 ;
     RECT  17.123 9.84 18.061 10.104 ;
     RECT  17.201 28.512 18.097 28.632 ;
     RECT  17.129 15.024 18.169 15.048 ;
     RECT  17.521 16.416 18.169 17.16 ;
     RECT  18.025 18.432 18.205 18.696 ;
     RECT  18.169 15.024 18.229 17.16 ;
     RECT  18.205 18.432 18.241 19.32 ;
     RECT  18.061 9.84 18.277 10.44 ;
     RECT  18.241 18.336 18.277 19.32 ;
     RECT  17.485 21.12 18.277 21.192 ;
     RECT  18.277 20.64 18.349 21.192 ;
     RECT  17.237 23.328 18.385 23.352 ;
     RECT  18.385 23.328 18.529 23.88 ;
     RECT  18.277 9.84 18.601 10.824 ;
     RECT  17.773 0.912 18.608 6.984 ;
     RECT  18.061 7.968 18.608 8.52 ;
     RECT  18.601 9.84 18.608 11.208 ;
     RECT  17.737 12.24 18.608 13.224 ;
     RECT  18.229 14.976 18.608 17.16 ;
     RECT  18.277 18.24 18.608 19.32 ;
     RECT  18.349 20.592 18.608 21.192 ;
     RECT  18.529 23.328 18.608 23.928 ;
     RECT  17.633 25.104 18.608 25.224 ;
     RECT  17.605 26.304 18.608 26.856 ;
     RECT  18.097 27.984 18.608 28.632 ;
     RECT  17.633 30.096 18.608 30.936 ;
     RECT  15.395 33.84 18.608 34.68 ;
     RECT  13.504 37.68 18.608 37.704 ;
     RECT  18.608 0.912 18.712 69.132 ;
     RECT  18.712 0.912 18.904 68.862 ;
     RECT  18.904 33.84 19.043 34.68 ;
     RECT  18.904 7.968 19.073 12.456 ;
     RECT  18.904 14.832 19.091 15.048 ;
     RECT  18.904 0.912 19.253 6.888 ;
     RECT  19.073 7.968 19.283 12.072 ;
     RECT  19.283 7.968 19.379 8.952 ;
     RECT  19.283 9.984 19.397 12.072 ;
     RECT  18.904 16.416 19.427 19.32 ;
     RECT  18.904 24.528 19.433 28.008 ;
     RECT  18.904 21.696 19.541 23.4 ;
     RECT  19.541 21.696 19.721 21.72 ;
     RECT  19.427 16.416 19.785 17.496 ;
     RECT  19.433 24.528 19.829 27.384 ;
     RECT  19.253 0.912 19.901 6.696 ;
     RECT  19.829 24.528 19.907 26.232 ;
     RECT  19.901 0.912 19.909 6.168 ;
     RECT  19.541 23.28 19.916 23.4 ;
     RECT  19.907 24.528 19.916 24.552 ;
     RECT  19.785 16.416 19.937 16.968 ;
     RECT  19.937 16.416 19.957 16.632 ;
     RECT  19.397 9.984 19.973 11.4 ;
     RECT  19.427 18.672 19.973 19.32 ;
     RECT  19.907 25.776 19.973 26.232 ;
     RECT  19.829 27.36 19.973 27.384 ;
     RECT  19.889 28.464 19.973 28.488 ;
     RECT  19.043 33.84 19.973 33.864 ;
     RECT  18.904 29.664 20.001 29.688 ;
     RECT  19.916 23.28 20.003 24.552 ;
     RECT  19.957 21.168 20.005 21.192 ;
     RECT  19.957 16.224 20.009 16.632 ;
     RECT  20.009 16.224 20.044 16.248 ;
     RECT  19.973 10.08 20.045 11.4 ;
     RECT  19.909 0.864 20.077 6.168 ;
     RECT  19.973 18.672 20.081 19.128 ;
     RECT  20.005 21.072 20.081 21.192 ;
     RECT  20.081 21.072 20.117 21.096 ;
     RECT  19.379 7.968 20.195 8.904 ;
     RECT  20.195 8.496 20.236 8.904 ;
     RECT  19.091 14.832 20.369 14.952 ;
     RECT  20.003 23.28 20.405 23.352 ;
     RECT  20.405 23.328 20.477 23.352 ;
     RECT  18.904 37.68 20.483 37.704 ;
     RECT  20.236 8.496 20.549 8.52 ;
     RECT  20.081 18.768 20.585 19.128 ;
     RECT  20.369 14.832 20.621 14.856 ;
     RECT  20.585 18.768 20.621 18.84 ;
     RECT  20.045 10.08 20.729 10.92 ;
     RECT  20.729 10.176 20.873 10.92 ;
     RECT  20.077 0.816 20.977 6.168 ;
     RECT  20.873 10.896 20.981 10.92 ;
     RECT  20.621 18.816 21.125 18.84 ;
     RECT  19.973 26.112 21.161 26.136 ;
     RECT  20.977 0.528 21.589 6.168 ;
     RECT  20.437 33.936 21.593 34.152 ;
     RECT  21.589 0.48 22.525 6.168 ;
     RECT  22.525 0.432 22.597 6.168 ;
     RECT  22.597 0.432 22.921 6.696 ;
     RECT  22.921 0.432 23.317 6.888 ;
     RECT  23.317 0.432 23.832 6.984 ;
     RECT  24.008 67.488 24.112 69.132 ;
     RECT  24.112 67.488 24.2 68.862 ;
     RECT  24.2 67.218 24.304 68.862 ;
     RECT  29.408 67.488 29.512 69.132 ;
     RECT  29.512 67.488 29.6 68.862 ;
     RECT  29.6 67.218 29.704 68.862 ;
     RECT  34.808 67.488 34.912 69.132 ;
     RECT  34.912 67.488 35 68.862 ;
     RECT  35 67.218 35.104 68.862 ;
     RECT  40.208 67.488 40.312 69.132 ;
     RECT  40.312 67.488 40.4 68.862 ;
     RECT  40.4 67.218 40.504 68.862 ;
     RECT  45.608 67.488 45.712 69.132 ;
     RECT  45.712 67.488 45.8 68.862 ;
     RECT  45.8 67.218 45.904 68.862 ;
     RECT  51.008 67.488 51.112 69.132 ;
     RECT  51.112 67.488 51.2 68.862 ;
     RECT  51.2 67.218 51.304 68.862 ;
     RECT  56.408 67.488 56.512 69.132 ;
     RECT  56.512 67.488 56.6 68.862 ;
     RECT  56.6 67.218 56.704 68.862 ;
     RECT  23.832 0.432 61.728 65.112 ;
     RECT  61.808 67.488 61.912 69.132 ;
     RECT  61.912 67.488 62 68.862 ;
     RECT  62 67.218 62.104 68.862 ;
     RECT  61.728 0.432 62.579 6.984 ;
     RECT  62.579 4.848 62.627 6.984 ;
     RECT  62.627 5.52 62.741 6.984 ;
     RECT  62.579 0.432 62.777 3.432 ;
     RECT  62.777 0.768 62.867 3.432 ;
     RECT  62.867 0.864 62.885 3.432 ;
     RECT  62.885 0.864 62.915 0.888 ;
     RECT  62.741 5.616 63.065 6.984 ;
     RECT  63.065 5.712 63.605 6.984 ;
     RECT  64.033 9.216 64.117 9.24 ;
     RECT  64.117 9.12 64.211 9.24 ;
     RECT  64.165 7.92 64.253 7.944 ;
     RECT  61.728 12.624 64.253 12.648 ;
     RECT  64.465 28.512 64.549 28.536 ;
     RECT  64.033 15.072 64.691 15.096 ;
     RECT  64.604 16.944 64.691 16.968 ;
     RECT  64.177 20.448 64.691 20.472 ;
     RECT  64.537 11.424 64.787 11.448 ;
     RECT  63.605 5.712 64.789 6.888 ;
     RECT  62.885 1.92 65.009 3.096 ;
     RECT  64.211 9.12 65.009 9.144 ;
     RECT  64.789 5.712 65.117 7.464 ;
     RECT  65.117 6.288 65.225 7.464 ;
     RECT  65.009 1.968 65.276 3.096 ;
     RECT  64.969 14.832 65.315 14.856 ;
     RECT  65.225 6.288 65.333 6.888 ;
     RECT  65.276 1.968 65.363 3.432 ;
     RECT  65.113 19.968 65.363 19.992 ;
     RECT  65.363 1.968 65.411 3.24 ;
     RECT  65.293 13.104 65.411 13.128 ;
     RECT  65.333 6.288 65.459 6.312 ;
     RECT  65.411 1.968 65.513 3.096 ;
     RECT  65.513 1.968 65.891 2.28 ;
     RECT  65.545 16.56 65.891 16.584 ;
     RECT  65.891 1.968 66.053 1.992 ;
     RECT  67.208 2.148 67.312 69.132 ;
     RECT  67.312 2.418 67.504 68.862 ;
     RECT  72.608 2.148 72.712 69.132 ;
     RECT  72.712 2.418 72.904 68.862 ;
     RECT  78.008 2.148 78.112 69.132 ;
     RECT  78.112 2.418 78.304 68.862 ;
    LAYER M5 ;
     RECT  21.6 0.469 21.624 0.709 ;
     RECT  61.968 0.469 61.992 0.709 ;
     RECT  21.024 0.709 21.624 0.757 ;
     RECT  61.584 0.709 61.992 0.757 ;
     RECT  61.584 0.757 62.856 0.853 ;
     RECT  61.584 0.853 62.904 2.003 ;
     RECT  19.92 0.853 19.944 2.005 ;
     RECT  17.616 1.573 17.64 2.137 ;
     RECT  19.2 2.005 19.944 2.137 ;
     RECT  2.4 2.137 2.52 2.151 ;
     RECT  7.8 2.137 7.92 2.151 ;
     RECT  13.2 2.137 13.32 2.151 ;
     RECT  67.2 2.137 67.32 2.151 ;
     RECT  72.6 2.137 72.72 2.151 ;
     RECT  78 2.137 78.12 2.151 ;
     RECT  17.616 2.137 19.944 2.245 ;
     RECT  21.024 0.757 21.672 2.245 ;
     RECT  17.616 2.245 21.672 2.579 ;
     RECT  61.8 2.003 62.904 2.723 ;
     RECT  17.616 2.579 20.472 2.915 ;
     RECT  21.6 2.579 21.672 2.915 ;
     RECT  15.36 2.245 15.384 3.061 ;
     RECT  61.8 2.723 62.856 3.107 ;
     RECT  21.6 2.915 21.624 3.443 ;
     RECT  15.36 3.061 15.48 3.541 ;
     RECT  61.8 3.107 62.616 4.883 ;
     RECT  63.984 2.245 65.88 5.747 ;
     RECT  13.2 2.151 13.512 7.189 ;
     RECT  7.8 2.151 8.112 7.909 ;
     RECT  17.616 2.915 19.848 7.957 ;
     RECT  17.616 7.957 20.184 8.485 ;
     RECT  13.2 7.189 14.136 9.109 ;
     RECT  17.088 8.485 20.184 9.109 ;
     RECT  64.128 5.747 65.88 9.155 ;
     RECT  64.176 9.155 65.88 9.251 ;
     RECT  11.088 5.845 11.112 9.299 ;
     RECT  13.104 9.109 14.136 9.829 ;
     RECT  16.992 9.109 20.184 10.069 ;
     RECT  16.56 10.069 20.184 10.115 ;
     RECT  17.616 10.115 20.184 10.883 ;
     RECT  6.768 9.637 6.792 10.933 ;
     RECT  7.8 7.909 8.328 10.933 ;
     RECT  6.768 10.933 8.328 10.979 ;
     RECT  64.752 9.251 65.88 11.459 ;
     RECT  16.56 10.115 16.584 11.555 ;
     RECT  6.768 10.979 8.112 12.611 ;
     RECT  13.056 9.829 14.136 13.045 ;
     RECT  11.952 12.325 11.976 13.331 ;
     RECT  10.272 12.853 10.296 14.101 ;
     RECT  10.272 14.101 10.392 14.147 ;
     RECT  15.36 3.541 15.576 14.677 ;
     RECT  6.768 12.611 6.792 14.725 ;
     RECT  7.8 12.611 8.112 14.725 ;
     RECT  17.616 10.883 19.848 14.821 ;
     RECT  65.28 11.459 65.88 15.061 ;
     RECT  15.36 14.677 15.96 15.107 ;
     RECT  11.856 14.917 11.88 15.443 ;
     RECT  6.768 14.725 8.112 15.445 ;
     RECT  5.808 15.445 8.112 15.491 ;
     RECT  13.056 13.045 14.184 15.493 ;
     RECT  6.864 15.491 8.112 16.019 ;
     RECT  10.368 14.147 10.392 16.403 ;
     RECT  2.4 2.151 2.712 16.501 ;
     RECT  12.336 15.493 14.184 16.595 ;
     RECT  17.616 14.821 19.992 16.595 ;
     RECT  64.656 15.061 65.88 16.595 ;
     RECT  17.616 16.595 19.848 16.787 ;
     RECT  15.36 15.107 15.576 16.981 ;
     RECT  17.616 16.787 19.752 16.981 ;
     RECT  17.136 16.981 19.752 17.123 ;
     RECT  7.68 16.019 8.112 17.171 ;
     RECT  17.616 17.123 19.752 17.507 ;
     RECT  13.056 16.595 14.184 17.795 ;
     RECT  4.512 17.029 4.536 17.987 ;
     RECT  5.808 15.491 5.832 18.037 ;
     RECT  2.304 16.501 2.712 18.131 ;
     RECT  15.36 16.981 15.672 18.275 ;
     RECT  17.616 17.507 19.416 18.803 ;
     RECT  17.616 18.803 19.08 18.851 ;
     RECT  64.656 16.595 65.352 20.003 ;
     RECT  4.032 19.333 4.056 20.291 ;
     RECT  64.656 20.003 64.68 20.437 ;
     RECT  64.512 20.437 64.68 20.483 ;
     RECT  2.4 18.131 2.712 20.965 ;
     RECT  5.808 18.037 5.976 21.155 ;
     RECT  17.616 18.851 19.032 21.157 ;
     RECT  20.448 19.093 20.472 21.157 ;
     RECT  7.8 17.171 8.112 21.493 ;
     RECT  5.952 21.155 5.976 21.589 ;
     RECT  13.104 17.795 14.184 22.021 ;
     RECT  15.36 18.275 15.576 22.021 ;
     RECT  5.952 21.589 6.12 22.307 ;
     RECT  5.952 22.307 6.072 22.403 ;
     RECT  2.304 20.965 2.712 22.835 ;
     RECT  4.56 21.781 4.584 22.835 ;
     RECT  7.8 21.493 8.472 22.835 ;
     RECT  13.104 22.021 15.576 23.461 ;
     RECT  13.008 23.461 15.576 23.987 ;
     RECT  17.616 21.157 20.472 25.093 ;
     RECT  10.608 21.493 10.632 25.139 ;
     RECT  6.048 22.403 6.072 25.717 ;
     RECT  7.8 22.835 8.112 25.717 ;
     RECT  17.52 25.093 20.472 25.811 ;
     RECT  6.048 25.717 8.472 26.003 ;
     RECT  13.104 23.987 15.576 26.243 ;
     RECT  6.912 26.003 8.472 26.675 ;
     RECT  5.664 26.005 5.688 26.725 ;
     RECT  6.912 26.675 8.112 26.867 ;
     RECT  4.752 26.725 5.688 27.781 ;
     RECT  13.104 26.243 14.184 27.923 ;
     RECT  17.52 25.811 19.032 28.453 ;
     RECT  20.448 25.811 20.472 28.453 ;
     RECT  4.704 27.781 5.688 28.547 ;
     RECT  64.512 20.483 64.536 28.547 ;
     RECT  17.52 28.453 20.472 28.643 ;
     RECT  2.4 22.835 2.712 29.029 ;
     RECT  13.104 27.923 13.992 29.605 ;
     RECT  17.616 28.643 20.472 29.699 ;
     RECT  2.4 29.029 2.808 29.795 ;
     RECT  9.12 29.029 9.144 29.891 ;
     RECT  10.944 26.341 10.968 30.803 ;
     RECT  5.376 28.547 5.688 30.805 ;
     RECT  9.264 30.181 9.288 31.333 ;
     RECT  5.136 30.805 5.688 31.379 ;
     RECT  9.264 31.333 9.672 31.427 ;
     RECT  12.24 29.605 13.992 31.523 ;
     RECT  5.376 31.379 5.688 31.907 ;
     RECT  3.744 31.285 3.768 32.195 ;
     RECT  9.6 31.427 9.672 32.771 ;
     RECT  12.24 31.523 13.656 32.771 ;
     RECT  13.104 32.771 13.656 33.395 ;
     RECT  5.664 31.907 5.688 33.829 ;
     RECT  5.136 33.829 5.688 33.875 ;
     RECT  9.648 32.771 9.672 34.067 ;
     RECT  10.896 32.293 10.92 34.259 ;
     RECT  15.36 26.243 15.576 34.403 ;
     RECT  17.616 29.699 19.032 34.451 ;
     RECT  5.136 33.875 5.16 34.547 ;
     RECT  13.104 33.395 13.608 34.643 ;
     RECT  13.2 34.643 13.608 34.691 ;
     RECT  18.6 34.451 19.032 34.691 ;
     RECT  12.144 34.645 12.168 34.835 ;
     RECT  15.36 34.403 15.384 35.027 ;
     RECT  7.8 26.867 8.112 35.845 ;
     RECT  9.6 34.165 9.624 35.845 ;
     RECT  10.944 35.317 10.968 35.939 ;
     RECT  7.8 35.845 9.624 36.515 ;
     RECT  20.448 29.699 20.472 37.715 ;
     RECT  9.6 36.515 9.624 38.149 ;
     RECT  9.36 38.149 9.624 38.195 ;
     RECT  6.432 39.541 6.456 40.739 ;
     RECT  4.32 36.421 4.344 41.891 ;
     RECT  9.36 38.195 9.384 43.043 ;
     RECT  5.76 42.997 5.784 43.045 ;
     RECT  7.8 36.515 8.112 44.437 ;
     RECT  4.848 43.045 5.784 45.109 ;
     RECT  4.56 45.109 5.784 45.155 ;
     RECT  7.488 44.437 8.112 46.211 ;
     RECT  4.56 45.155 4.584 47.363 ;
     RECT  5.76 45.155 5.784 49.237 ;
     RECT  4.56 52.789 4.584 53.603 ;
     RECT  5.76 49.237 6.456 54.085 ;
     RECT  4.848 54.085 6.456 54.179 ;
     RECT  7.8 46.211 8.112 54.181 ;
     RECT  2.4 29.795 2.712 55.813 ;
     RECT  4.848 54.179 5.784 55.859 ;
     RECT  7.8 54.181 8.232 57.635 ;
     RECT  2.4 55.813 3.24 58.163 ;
     RECT  5.76 55.859 5.784 59.797 ;
     RECT  5.088 59.797 5.784 61.619 ;
     RECT  5.088 61.619 5.112 61.667 ;
     RECT  6.096 62.101 6.12 63.299 ;
     RECT  2.4 58.163 2.712 69.129 ;
     RECT  7.8 57.635 8.112 69.129 ;
     RECT  13.2 34.691 13.512 69.129 ;
     RECT  18.6 34.691 18.912 69.129 ;
     RECT  24 2.151 24.312 69.129 ;
     RECT  29.4 2.151 29.712 69.129 ;
     RECT  34.8 2.151 35.112 69.129 ;
     RECT  40.2 2.151 40.512 69.129 ;
     RECT  45.6 2.151 45.912 69.129 ;
     RECT  51 2.151 51.312 69.129 ;
     RECT  56.4 2.151 56.712 69.129 ;
     RECT  61.8 4.883 62.112 69.129 ;
     RECT  67.2 2.151 67.512 69.129 ;
     RECT  72.6 2.151 72.912 69.129 ;
     RECT  78 2.151 78.312 69.129 ;
     RECT  2.4 69.129 2.52 69.143 ;
     RECT  7.8 69.129 7.92 69.143 ;
     RECT  13.2 69.129 13.32 69.143 ;
     RECT  18.6 69.129 18.72 69.143 ;
     RECT  24 69.129 24.12 69.143 ;
     RECT  29.4 69.129 29.52 69.143 ;
     RECT  34.8 69.129 34.92 69.143 ;
     RECT  40.2 69.129 40.32 69.143 ;
     RECT  45.6 69.129 45.72 69.143 ;
     RECT  51 69.129 51.12 69.143 ;
     RECT  56.4 69.129 56.52 69.143 ;
     RECT  61.8 69.129 61.92 69.143 ;
     RECT  67.2 69.129 67.32 69.143 ;
     RECT  72.6 69.129 72.72 69.143 ;
     RECT  78 69.129 78.12 69.143 ;
     RECT  19.944 0.853 21.024 2.245 ;
     RECT  62.904 2.245 63.984 2.723 ;
     RECT  65.88 2.245 67.2 16.595 ;
     RECT  20.472 2.579 21.6 2.915 ;
     RECT  62.856 2.723 63.984 3.107 ;
     RECT  62.616 3.107 63.984 4.883 ;
     RECT  14.136 7.189 15.36 13.045 ;
     RECT  15.576 8.485 17.088 9.109 ;
     RECT  15.576 9.109 16.992 10.069 ;
     RECT  6.792 9.637 7.8 10.933 ;
     RECT  15.576 10.069 16.56 11.555 ;
     RECT  16.584 10.115 17.616 11.555 ;
     RECT  11.976 12.325 13.056 13.331 ;
     RECT  6.792 12.611 7.8 14.725 ;
     RECT  14.184 13.045 15.36 22.021 ;
     RECT  10.392 14.917 11.856 15.443 ;
     RECT  11.88 14.917 13.056 15.443 ;
     RECT  12.336 15.443 13.056 15.493 ;
     RECT  5.832 15.491 6.864 16.019 ;
     RECT  15.672 16.981 17.136 17.123 ;
     RECT  4.536 17.029 5.808 17.987 ;
     RECT  19.08 18.803 19.416 18.851 ;
     RECT  19.032 18.851 19.416 19.093 ;
     RECT  19.032 19.093 20.448 21.157 ;
     RECT  2.712 19.333 4.032 20.291 ;
     RECT  5.808 21.155 5.952 21.781 ;
     RECT  4.584 21.781 5.952 22.403 ;
     RECT  4.584 22.403 6.048 22.835 ;
     RECT  19.032 25.811 20.448 28.453 ;
     RECT  6.048 26.003 6.912 26.005 ;
     RECT  5.688 26.005 6.912 26.867 ;
     RECT  14.184 26.243 15.36 27.923 ;
     RECT  13.992 27.923 15.36 31.523 ;
     RECT  8.112 29.029 9.12 29.891 ;
     RECT  10.968 29.605 12.24 30.803 ;
     RECT  19.032 29.699 20.448 34.691 ;
     RECT  2.712 29.795 2.808 31.285 ;
     RECT  8.112 29.891 9.144 30.181 ;
     RECT  8.112 30.181 9.264 31.427 ;
     RECT  10.944 30.803 12.24 31.333 ;
     RECT  2.712 31.285 3.744 32.195 ;
     RECT  3.768 31.285 5.136 31.379 ;
     RECT  9.672 31.333 12.24 32.293 ;
     RECT  8.112 31.427 9.6 32.771 ;
     RECT  9.672 32.293 10.896 34.067 ;
     RECT  10.92 32.293 12.24 32.771 ;
     RECT  8.112 32.771 9.648 34.067 ;
     RECT  8.112 34.067 10.896 34.165 ;
     RECT  8.112 34.165 9.6 35.845 ;
     RECT  9.624 34.165 10.896 34.259 ;
     RECT  9.624 34.259 10.92 34.645 ;
     RECT  13.104 34.643 13.2 34.645 ;
     RECT  9.624 34.645 12.144 34.835 ;
     RECT  12.168 34.645 13.2 34.835 ;
     RECT  9.624 34.835 10.968 35.317 ;
     RECT  9.624 35.317 10.944 35.939 ;
     RECT  8.112 36.515 9.6 38.149 ;
     RECT  8.112 38.149 9.36 43.043 ;
     RECT  6.456 39.541 7.8 40.739 ;
     RECT  4.584 45.155 5.76 47.363 ;
     RECT  6.456 49.237 7.8 54.179 ;
     RECT  4.584 52.789 5.76 53.603 ;
     RECT  4.848 53.603 5.76 54.085 ;
  END
END qfd_sys_face_mu_dhuser
END LIBRARY
